Omron CX-Programmer project NewProject (CX-Programmer 9.33)

# PLC NewPLC1: CJ1M CPU13
I/O table (CPU CJ1M-CPU13): rack 0 slot 0 CJ1W-ID211; rack 0 slot 1 CJ1W-OC211; rack 0 slot 2 CJ1W-SCU32

## Global symbols (name address type ; comment)
1919.15 BOOL  ; $?St$Bk?_#[6] / Port 2 Protocol Macro Execution Flag / $?St$Bk?_#[6]
A202.00 BOOL  ; Communications Port Enabled Flag
A202.01 BOOL  ; Communications Port Enabled Flag
W0.00 BOOL  ; Execute Reading PV Of E5CN
W0.01 BOOL  ; Execute Writing SP Of E5CN
V1000_MoveVelocityHz_Node10 INV032_MoveVelocityHz
V1000_ReadParameter_Node10 INV201_ReadParameter
V1000_ReadStatus_Node10 INV200_ReadStatus
V1000_Refresh_Node10 INV002_Refresh
V1000_Reset_Node10 INV080_Reset
V1000_Stop_Node10 INV060_Stop

## Program NewProgram1 (cyclic task 0)

### Section E5CN

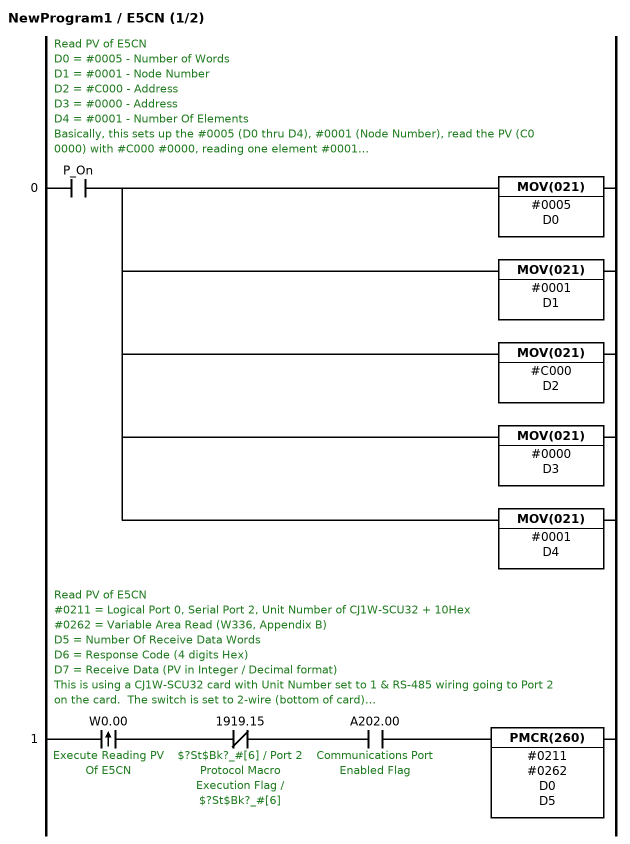
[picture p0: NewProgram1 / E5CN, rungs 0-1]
; rung 0: Read PV of E5CN / D0 = #0005 - Number of Words / D1 = #0001 - Node Number / D2 = #C000 - Address / D3 = #0000 - Address / D4 = #0001 - Number Of Elements / Basically, this sets up the #0005 (D0 thru D4), #0001 (Node Number), read the PV (C0 0000) with #C000 #0000, reading one element #0001. / C0 0000 is from manual H158, Section 3.1. / This rungs sets up the data for receiving the PV of the E5CN temperature controller at Node number 1 over Compoway/F communications.
LD P_On
MOV(021) #0005 D0
MOV(021) #0001 D1
MOV(021) #C000 D2
MOV(021) #0000 D3
MOV(021) #0001 D4
; rung 1: Read PV of E5CN / #0211 = Logical Port 0, Serial Port 2, Unit Number of CJ1W-SCU32 + 10Hex / #0262 = Variable Area Read (W336, Appendix B) / D5 = Number Of Receive Data Words / D6 = Response Code (4 digits Hex) / D7 = Receive Data (PV in Integer / Decimal format) / This is using a CJ1W-SCU32 card with Unit Number set to 1 & RS-485 wiring going to Port 2 on the card.  The switch is set to 2-wire (bottom of card). / Port Settings - User Settings / Serial Communications Mode - Protocol Macro / Data Length - 7 Bits / Stop Bits - 2 Bits / Parity - Even / Baud Rate - 9600
@LD W0.00  ; Execute Reading PV Of E5CN
ANDNOT 1919.15  ; $?St$Bk?_#[6] / Port 2 Protocol Macro Execution Flag / $?St$Bk?_#[6]
AND A202.00  ; Communications Port Enabled Flag
PMCR(260) #0211 #0262 D0 D5

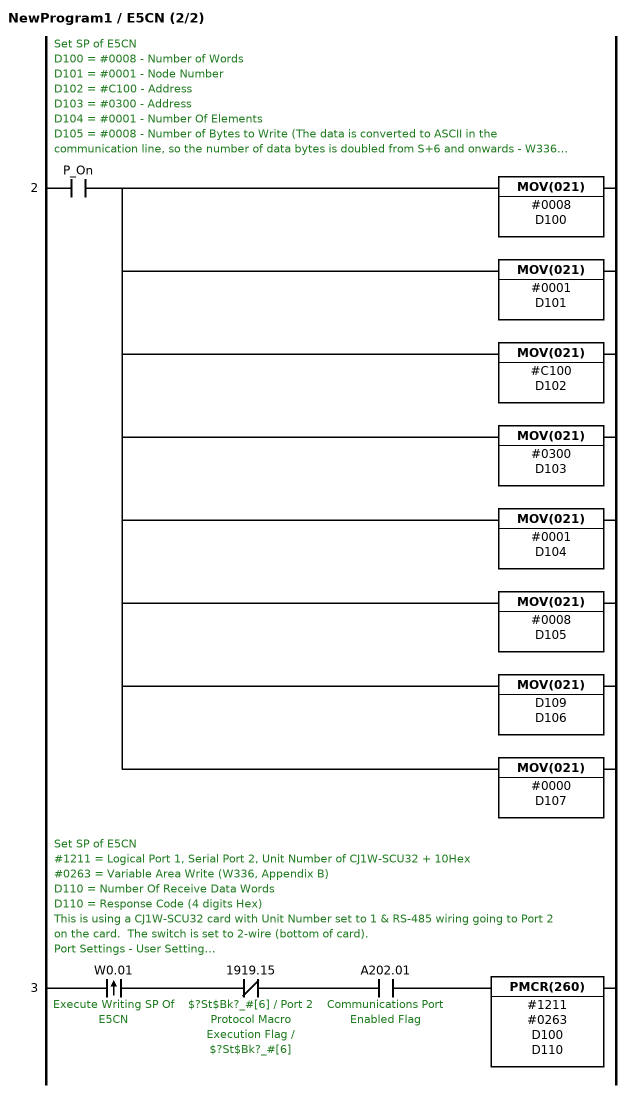
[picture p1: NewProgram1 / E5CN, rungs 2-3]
; rung 2: Set SP of E5CN / D100 = #0008 - Number of Words / D101 = #0001 - Node Number / D102 = #C100 - Address / D103 = #0300 - Address / D104 = #0001 - Number Of Elements / D105 = #0008 - Number of Bytes to Write (The data is converted to ASCII in the communication line, so the number of data bytes is doubled from S+6 and onwards - W336, Appendix B.) / D106 = D109 - LSW - Most Significant Word (Temperature Setpoint) / D107 = #0000 - MSW (Temperature Setpoint) / Basically, this sets up the #0008 (D100 thru D107), #0001 (Node Number), write the SP (C1 0003) with #C100 #0300, writing one element #0001. / C1 0003 is from manual H158, Section 3.1. / The data entered into D109 is in Integer / Decimal format. / This rungs sets up the data for sending the SP of the E5CN temperature controller at Node number 1 over Compoway/F communications.
LD P_On
MOV(021) #0008 D100
MOV(021) #0001 D101
MOV(021) #C100 D102
MOV(021) #0300 D103
MOV(021) #0001 D104
MOV(021) #0008 D105
MOV(021) D109 D106
MOV(021) #0000 D107
; rung 3: Set SP of E5CN / #1211 = Logical Port 1, Serial Port 2, Unit Number of CJ1W-SCU32 + 10Hex / #0263 = Variable Area Write (W336, Appendix B) / D110 = Number Of Receive Data Words / D110 = Response Code (4 digits Hex) / This is using a CJ1W-SCU32 card with Unit Number set to 1 & RS-485 wiring going to Port 2 on the card.  The switch is set to 2-wire (bottom of card). / Port Settings - User Settings / Serial Communications Mode - Protocol Macro / Data Length - 7 Bits / Stop Bits - 2 Bits / Parity - Even / Baud Rate - 9600
@LD W0.01  ; Execute Writing SP Of E5CN
ANDNOT 1919.15  ; $?St$Bk?_#[6] / Port 2 Protocol Macro Execution Flag / $?St$Bk?_#[6]
AND A202.01  ; Communications Port Enabled Flag
PMCR(260) #1211 #0263 D100 D110

### Section V1000

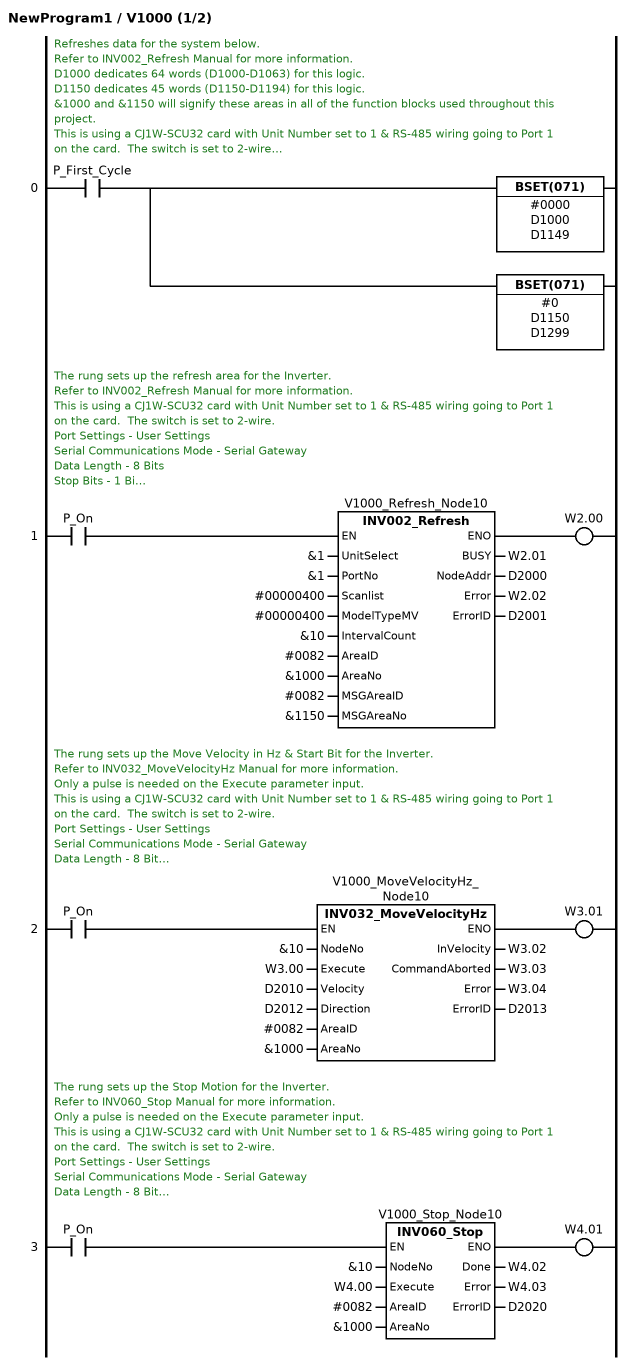
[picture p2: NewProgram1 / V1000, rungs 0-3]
; rung 0: Refreshes data for the system below. / Refer to INV002_Refresh Manual for more information. / D1000 dedicates 64 words (D1000-D1063) for this logic. / D1150 dedicates 45 words (D1150-D1194) for this logic. / &1000 and &1150 will signify these areas in all of the function blocks used throughout this project. / This is using a CJ1W-SCU32 card with Unit Number set to 1 & RS-485 wiring going to Port 1 on the card.  The switch is set to 2-wire. / Port Settings - User Settings / Serial Communications Mode - Serial Gateway / Data Length - 8 Bits / Stop Bits - 1 Bit / Parity - Even / Baud Rate - 9600
LD P_First_Cycle
BSET(071) #0000 D1000 D1149
BSET(071) #0 D1150 D1299
; rung 1: The rung sets up the refresh area for the Inverter. / Refer to INV002_Refresh Manual for more information. / This is using a CJ1W-SCU32 card with Unit Number set to 1 & RS-485 wiring going to Port 1 on the card.  The switch is set to 2-wire. / Port Settings - User Settings / Serial Communications Mode - Serial Gateway / Data Length - 8 Bits / Stop Bits - 1 Bit / Parity - Even / Baud Rate - 9600
LD P_On
CALL V1000_Refresh_Node10 : INV002_Refresh (UnitSelect := &1, PortNo := &1, Scanlist := #00000400, ModelTypeMV := #00000400, IntervalCount := &10, AreaID := #0082, AreaNo := &1000, MSGAreaID := #0082, MSGAreaNo := &1150, BUSY => W2.01, NodeAddr => D2000, Error => W2.02, ErrorID => D2001)
OUT W2.00
; rung 2: The rung sets up the Move Velocity in Hz & Start Bit for the Inverter. / Refer to INV032_MoveVelocityHz Manual for more information. / Only a pulse is needed on the Execute parameter input. / This is using a CJ1W-SCU32 card with Unit Number set to 1 & RS-485 wiring going to Port 1 on the card.  The switch is set to 2-wire. / Port Settings - User Settings / Serial Communications Mode - Serial Gateway / Data Length - 8 Bits / Stop Bits - 1 Bit / Parity - Even / Baud Rate - 9600
LD P_On
CALL V1000_MoveVelocityHz_Node10 : INV032_MoveVelocityHz (NodeNo := &10, Execute := W3.00, Velocity := D2010, Direction := D2012, AreaID := #0082, AreaNo := &1000, InVelocity => W3.02, CommandAborted => W3.03, Error => W3.04, ErrorID => D2013)
OUT W3.01
; rung 3: The rung sets up the Stop Motion for the Inverter. / Refer to INV060_Stop Manual for more information. / Only a pulse is needed on the Execute parameter input. / This is using a CJ1W-SCU32 card with Unit Number set to 1 & RS-485 wiring going to Port 1 on the card.  The switch is set to 2-wire. / Port Settings - User Settings / Serial Communications Mode - Serial Gateway / Data Length - 8 Bits / Stop Bits - 1 Bit / Parity - Even / Baud Rate - 9600
LD P_On
CALL V1000_Stop_Node10 : INV060_Stop (NodeNo := &10, Execute := W4.00, AreaID := #0082, AreaNo := &1000, Done => W4.02, Error => W4.03, ErrorID => D2020)
OUT W4.01

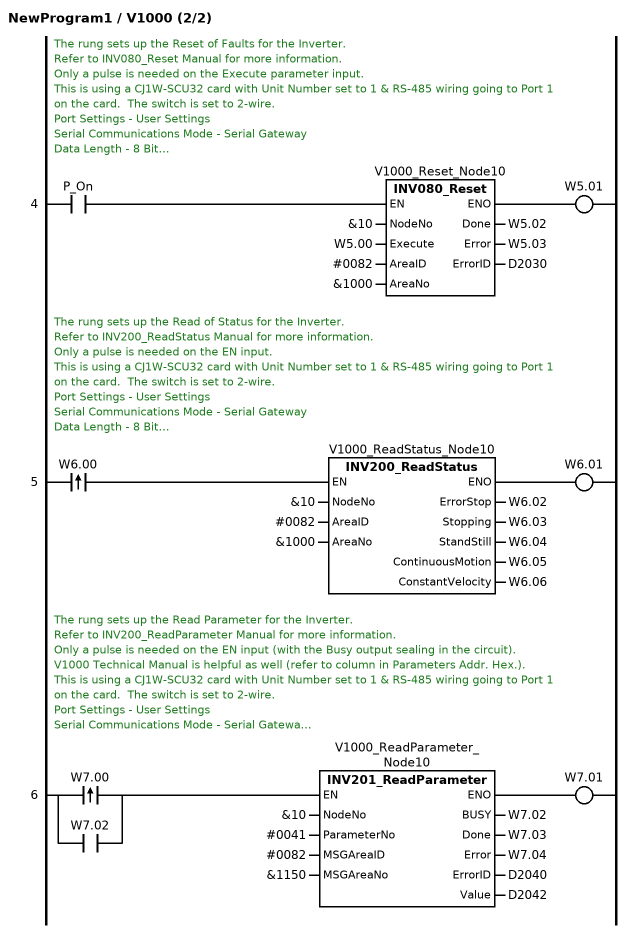
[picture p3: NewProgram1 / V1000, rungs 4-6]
; rung 4: The rung sets up the Reset of Faults for the Inverter. / Refer to INV080_Reset Manual for more information. / Only a pulse is needed on the Execute parameter input. / This is using a CJ1W-SCU32 card with Unit Number set to 1 & RS-485 wiring going to Port 1 on the card.  The switch is set to 2-wire. / Port Settings - User Settings / Serial Communications Mode - Serial Gateway / Data Length - 8 Bits / Stop Bits - 1 Bit / Parity - Even / Baud Rate - 9600
LD P_On
CALL V1000_Reset_Node10 : INV080_Reset (NodeNo := &10, Execute := W5.00, AreaID := #0082, AreaNo := &1000, Done => W5.02, Error => W5.03, ErrorID => D2030)
OUT W5.01
; rung 5: The rung sets up the Read of Status for the Inverter. / Refer to INV200_ReadStatus Manual for more information. / Only a pulse is needed on the EN input. / This is using a CJ1W-SCU32 card with Unit Number set to 1 & RS-485 wiring going to Port 1 on the card.  The switch is set to 2-wire. / Port Settings - User Settings / Serial Communications Mode - Serial Gateway / Data Length - 8 Bits / Stop Bits - 1 Bit / Parity - Even / Baud Rate - 9600
@LD W6.00
CALL V1000_ReadStatus_Node10 : INV200_ReadStatus (NodeNo := &10, AreaID := #0082, AreaNo := &1000, ErrorStop => W6.02, Stopping => W6.03, StandStill => W6.04, ContinuousMotion => W6.05, ConstantVelocity => W6.06)
OUT W6.01
; rung 6: The rung sets up the Read Parameter for the Inverter. / Refer to INV200_ReadParameter Manual for more information. / Only a pulse is needed on the EN input (with the Busy output sealing in the circuit). / V1000 Technical Manual is helpful as well (refer to column in Parameters Addr. Hex.). / This is using a CJ1W-SCU32 card with Unit Number set to 1 & RS-485 wiring going to Port 1 on the card.  The switch is set to 2-wire. / Port Settings - User Settings / Serial Communications Mode - Serial Gateway / Data Length - 8 Bits / Stop Bits - 1 Bit / Parity - Even / Baud Rate - 9600
@LD W7.00
OR W7.02
CALL V1000_ReadParameter_Node10 : INV201_ReadParameter (NodeNo := &10, ParameterNo := #0041, MSGAreaID := #0082, MSGAreaNo := &1150, BUSY => W7.02, Done => W7.03, Error => W7.04, ErrorID => D2040, Value => D2042)
OUT W7.01

### Section END
; rung 0
END(001)

## Function block INV002_Refresh
; <Status Refresh>Refreshes inverter status.
VAR_INPUT
  UnitSelect : INT;  (* Specify the connetcted Unit CP1CPU=#CCCC_SCB=#BBBB_SCU=&0 to &15 *)
  PortNo : INT := 1;  (* Serial port No. &1 to &2 *)
  Scanlist : DWORD;  (* Scanlist *)
  ModelTypeMV : DWORD;  (* MV/RV Classification *)
  IntervalCount : UINT;  (* Interval *)
  AreaID : WORD;  (* Using Area Classification *)
  AreaNo : INT;  (* Using Area Number *)
  MSGAreaID : WORD;  (* Message Area Classification *)
  MSGAreaNo : INT;  (* Message Area Number *)
END_VAR
VAR_OUTPUT
  BUSY : BOOL;  (* Processing Bit 0:Transferring Complete 1:Transferring *)
  NodeAddr : INT;  (* Executing Axis Number *)
  Error : BOOL;  (* Error *)
  ErrorID : WORD;  (* Error code *)
END_VAR
VAR
  AddressOk_Bit : BOOL;  (* Addrss Range Check OK Bit *)
  AreaID_Tmp : WORD;  (* Use Area Classification Memory (Internal Variables) *)
  AreaNo_Tmp : INT;  (* Use Area Number Memory (Internal Variables) *)
  BUSY_Run : BOOL;  (* Internal Processing Flag *)
  CMNDPort : INT;  (* Port Number 1(Automatic Setting) *)
  Command_CheckNo : INT;  (* Write Command Check Complete Number *)
  Command_Data : ARRAY[0..21] OF WORD;  (* CMND command data *)
  Command_Data_Change : BOOL;  (* Write Command Data Changing *)
  Command_Fin : BOOL;  (* CMND Transferring End *)
  Control_Data : ARRAY[0..5] OF WORD;  (* CMND control data *)
  Data_Change : BOOL;  (* Detect input data change *)
  Directive_Data : ARRAY[0..1] OF WORD;  (* Command data *)
  EM_NoCheck : INT;  (* EM bank size check area *)
  Error_Skip : BOOL;  (* Fatal Error Skip Flag *)
  FreeRunningCounter_Tmp : UINT;  (* 10ms free running incremental counter record *)
  Interval_Start : BOOL;  (* Interval Count Start *)
  Interval_TimeUp : BOOL;  (* Interval Time Up *)
  IntervalCount_Compare : INT;  (* Interval Compare Value *)
  IntervalCount_Tmp : UINT;  (* Interval Memory (Internal Variables) *)
  Inv_Command_Change_Position : INT;  (* Inverter Write Command Changing Position *)
  INV_Error : BOOL;  (* InverterNormal end *)
  Inv_NodeArea : ARRAY[0..31] OF WORD;  (* Applicable Axis Inverter Model and Number Store Area *)
  Inv_Status_Count : INT;  (* Inverter Status Command Execution Number *)
  Inv_Use_Count : INT;  (* Amount of Use Inverter Number *)
  Last_Area_Status : ARRAY[0..61] OF WORD;  (* The Last Time IOM Status Condition *)
  Message_Command_Done : BOOL;  (* Exist Message Command Flag *)
  ModelTypeMV_Tmp : DWORD;  (* MV/RV Classification Memory (Internal Variables) *)
  MSGAreaID_Tmp : WORD;  (* Message Area Classification Memory (Internal Variables) *)
  MSGAreaNo_Tmp : INT;  (* Message Area Number Memory (Internal Variables) *)
  NG_Bit : BOOL;  (* Range Check NG Bit *)
  No : INT;  (* MatrixNo *)
  Offset : DINT;  (* For Address Culcurate *)
  Ok_Bit : BOOL;  (* Range Check OK Bit *)
  Ok_DM : BOOL;  (* Selected DM area range OK *)
  Ok_EM : BOOL;  (* Selected EM area range OK *)
  Ok_HR : BOOL;  (* Selected HR area range OK *)
  Ok_IO : BOOL;  (* Selected CIO area range OK *)
  Ok_WR : BOOL;  (* Selected WR area range OK *)
  P_ComPort_AllocatedNumber AT A218 : INT;  (* Network port No. *)
  P_ComPort_AutoAlloc_Available AT A202.15 : BOOL;  (* Auto allocation avarable bit *)
  P_ComPort_Error AT A215 : WORD;  (* Communication Port No. 0 to 7 Error Bit *)
  P_ComPort_Finished0_7 AT A214 : WORD;  (* Communications Complete Cycle Bit *)
  P_ComPort_Retry AT A580 : WORD;  (* FB Communications command retry count *)
  P_ComPort_WatchResTime AT A581 : INT;  (* FB Communications command response Monitor time *)
  P_EM_MaxNo AT A338 : INT;  (* EM bank size *)
  P_Error : BOOL;  (* Error Bit *)
  P_FreeRunningCounter_10 AT A0 : UINT;  (* 10ms free running incremental counter *)
  Phase : WORD;  (* Process order *)
  PortNo_Tmp : INT;  (* Serial port No. storage(internal variables) *)
  Response_CodeNG : BOOL;  (* Response end code error *)
  Response_Data : ARRAY[0..20] OF WORD;  (* CMND response data *)
  Response_NG : BOOL;  (* Response error *)
  SaveDR : WORD;  (* DR0 *)
  SaveIR : ARRAY[0..3] OF DINT;  (* IR0 to IR3 *)
  Scanlist_Tmp : DWORD;  (* Scanlist Memory *)
  Set_IR AT 0 : WORD;  (* Index register temporary setting *)
  Status_2C : WORD;  (* Register2C  response data *)
  Status_Commmnd_Enable : BOOL;  (* Enable Execution Status Command *)
  Status_Commmnd_INT : BOOL;  (* Status Interrupt Flag *)
  Status_Inv_No : INT;  (* Status Command Slave Number *)
  Time_Value : UINT;  (* Interval Check Time Present Value *)
  Tmp_Data : ARRAY[0..30] OF WORD;  (* For internal Calculation *)
  Tmp_IR : ARRAY[0..3] OF DINT;  (* Temporary IR for internal variables *)
  Type_D AT D0 : WORD;  (* Address type DM start address *)
  Type_H AT H0 : WORD;  (* Address type HR start address *)
  Type_Io AT 0 : WORD;  (* Address type IO start address *)
  Type_W AT W0 : WORD;  (* Address type WR start address *)
  UnitSelect_Tmp : INT;  (* SCB/Select SCU Bit storage(internal variables) *)
  WAIT : BOOL;  (* First Cycle Wait Bit *)
END_VAR

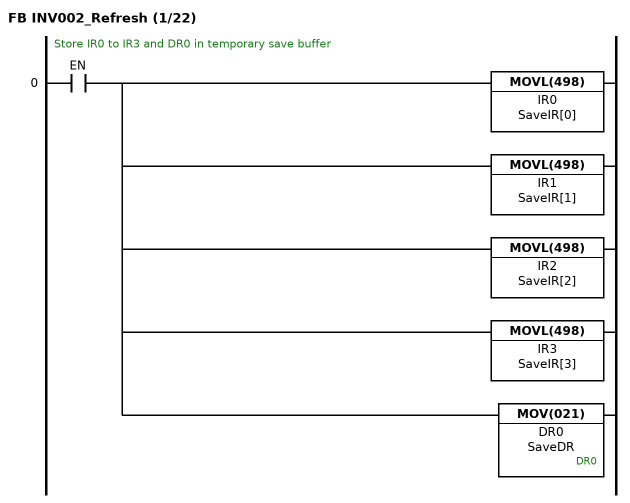
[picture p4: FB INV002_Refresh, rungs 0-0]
; rung 0: Store IR0 to IR3 and DR0 in temporary save buffer
LD EN
MOVL(498) IR0 SaveIR[0]
MOVL(498) IR1 SaveIR[1]
MOVL(498) IR2 SaveIR[2]
MOVL(498) IR3 SaveIR[3]
MOV(021) DR0 SaveDR  ; DR0

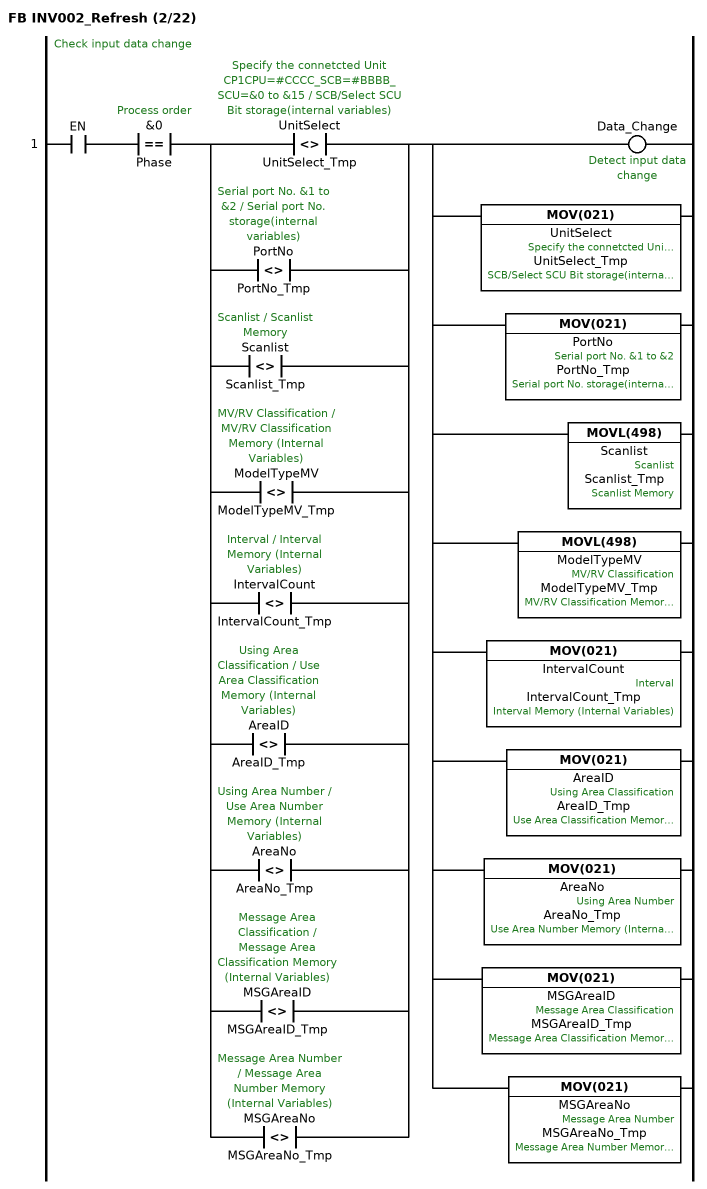
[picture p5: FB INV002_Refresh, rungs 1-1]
; rung 1: Check input data change
LD EN
AND=(300) &0 Phase  ; Process order
LD<>(305) UnitSelect UnitSelect_Tmp  ; Specify the connetcted Unit CP1CPU=#CCCC_SCB=#BBBB_SCU=&0 to &15, SCB/Select SCU Bit storage(internal variables)
OR<>(305) PortNo PortNo_Tmp  ; Serial port No. &1 to &2, Serial port No. storage(internal variables)
OR<>L(306) Scanlist Scanlist_Tmp  ; Scanlist, Scanlist Memory
OR<>L(306) ModelTypeMV ModelTypeMV_Tmp  ; MV/RV Classification, MV/RV Classification Memory (Internal Variables)
OR<>(305) IntervalCount IntervalCount_Tmp  ; Interval, Interval Memory (Internal Variables)
OR<>(305) AreaID AreaID_Tmp  ; Using Area Classification, Use Area Classification Memory (Internal Variables)
OR<>(305) AreaNo AreaNo_Tmp  ; Using Area Number, Use Area Number Memory (Internal Variables)
OR<>(305) MSGAreaID MSGAreaID_Tmp  ; Message Area Classification, Message Area Classification Memory (Internal Variables)
OR<>(305) MSGAreaNo MSGAreaNo_Tmp  ; Message Area Number, Message Area Number Memory (Internal Variables)
ANDLD
OUT Data_Change  ; Detect input data change
MOV(021) UnitSelect UnitSelect_Tmp  ; Specify the connetcted Unit CP1CPU=#CCCC_SCB=#BBBB_SCU=&0 to &15, SCB/Select SCU Bit storage(internal variables)
MOV(021) PortNo PortNo_Tmp  ; Serial port No. &1 to &2, Serial port No. storage(internal variables)
MOVL(498) Scanlist Scanlist_Tmp  ; Scanlist, Scanlist Memory
MOVL(498) ModelTypeMV ModelTypeMV_Tmp  ; MV/RV Classification, MV/RV Classification Memory (Internal Variables)
MOV(021) IntervalCount IntervalCount_Tmp  ; Interval, Interval Memory (Internal Variables)
MOV(021) AreaID AreaID_Tmp  ; Using Area Classification, Use Area Classification Memory (Internal Variables)
MOV(021) AreaNo AreaNo_Tmp  ; Using Area Number, Use Area Number Memory (Internal Variables)
MOV(021) MSGAreaID MSGAreaID_Tmp  ; Message Area Classification, Message Area Classification Memory (Internal Variables)
MOV(021) MSGAreaNo MSGAreaNo_Tmp  ; Message Area Number, Message Area Number Memory (Internal Variables)




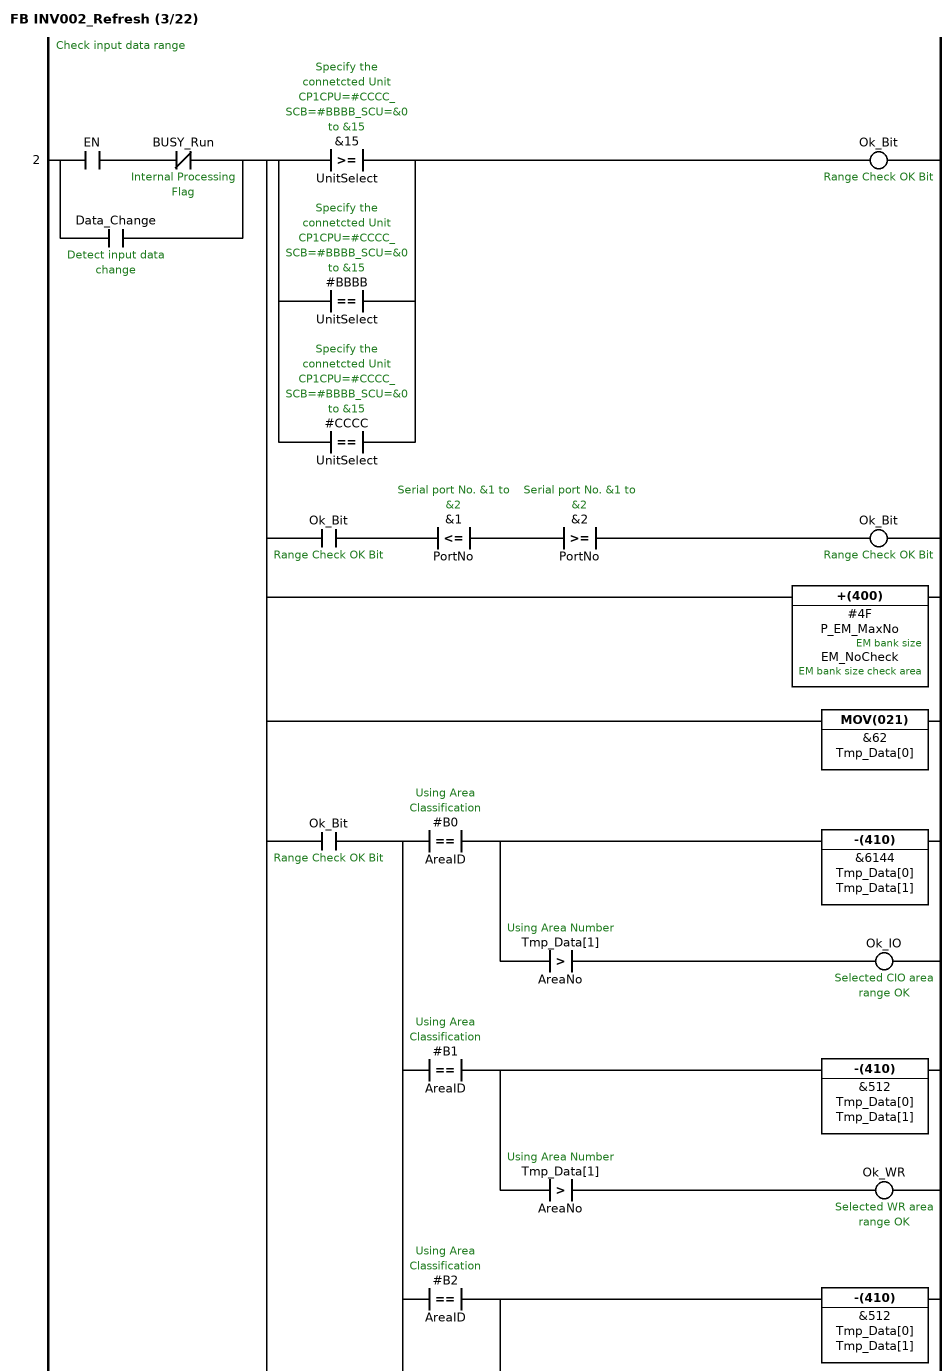
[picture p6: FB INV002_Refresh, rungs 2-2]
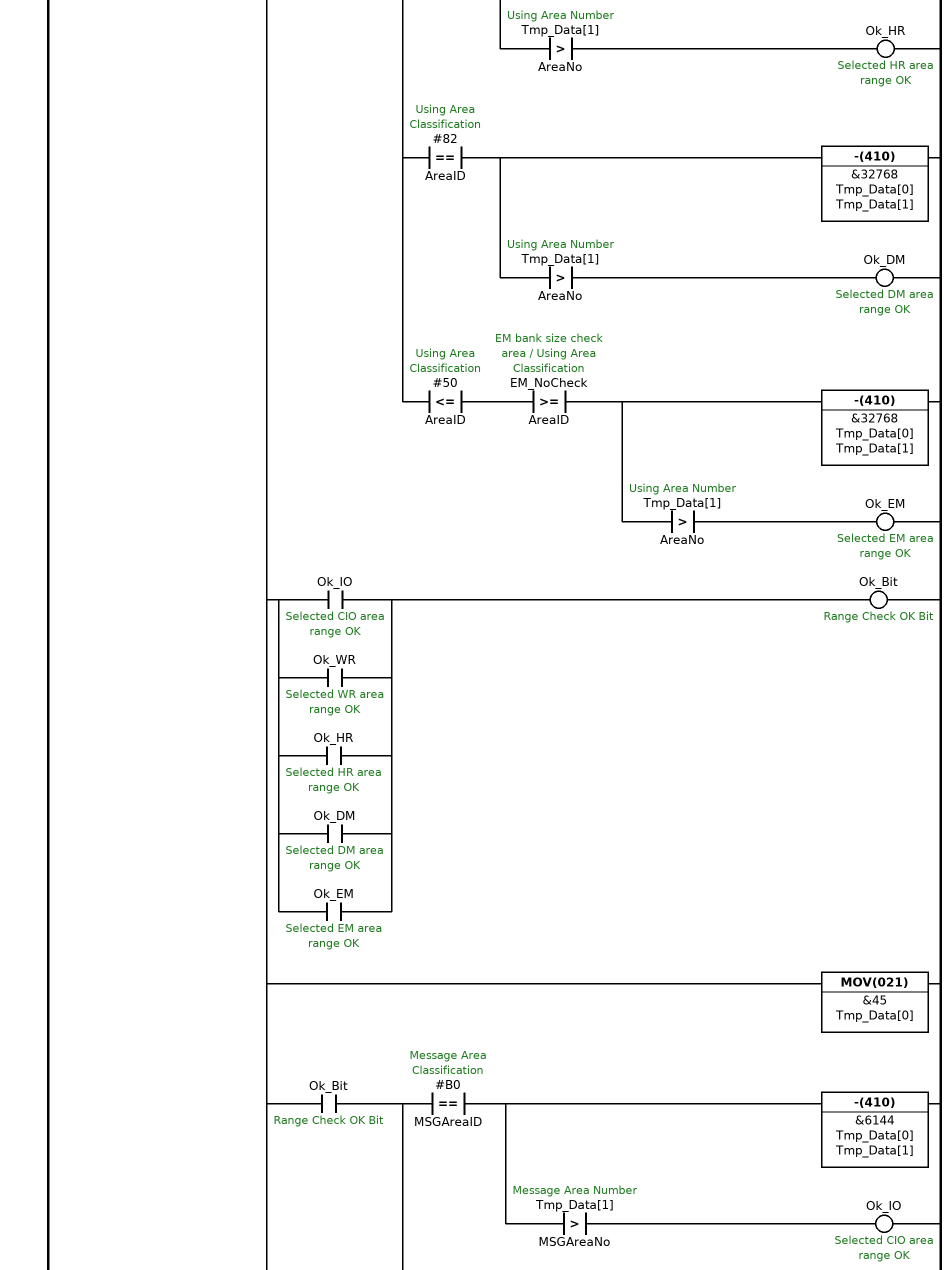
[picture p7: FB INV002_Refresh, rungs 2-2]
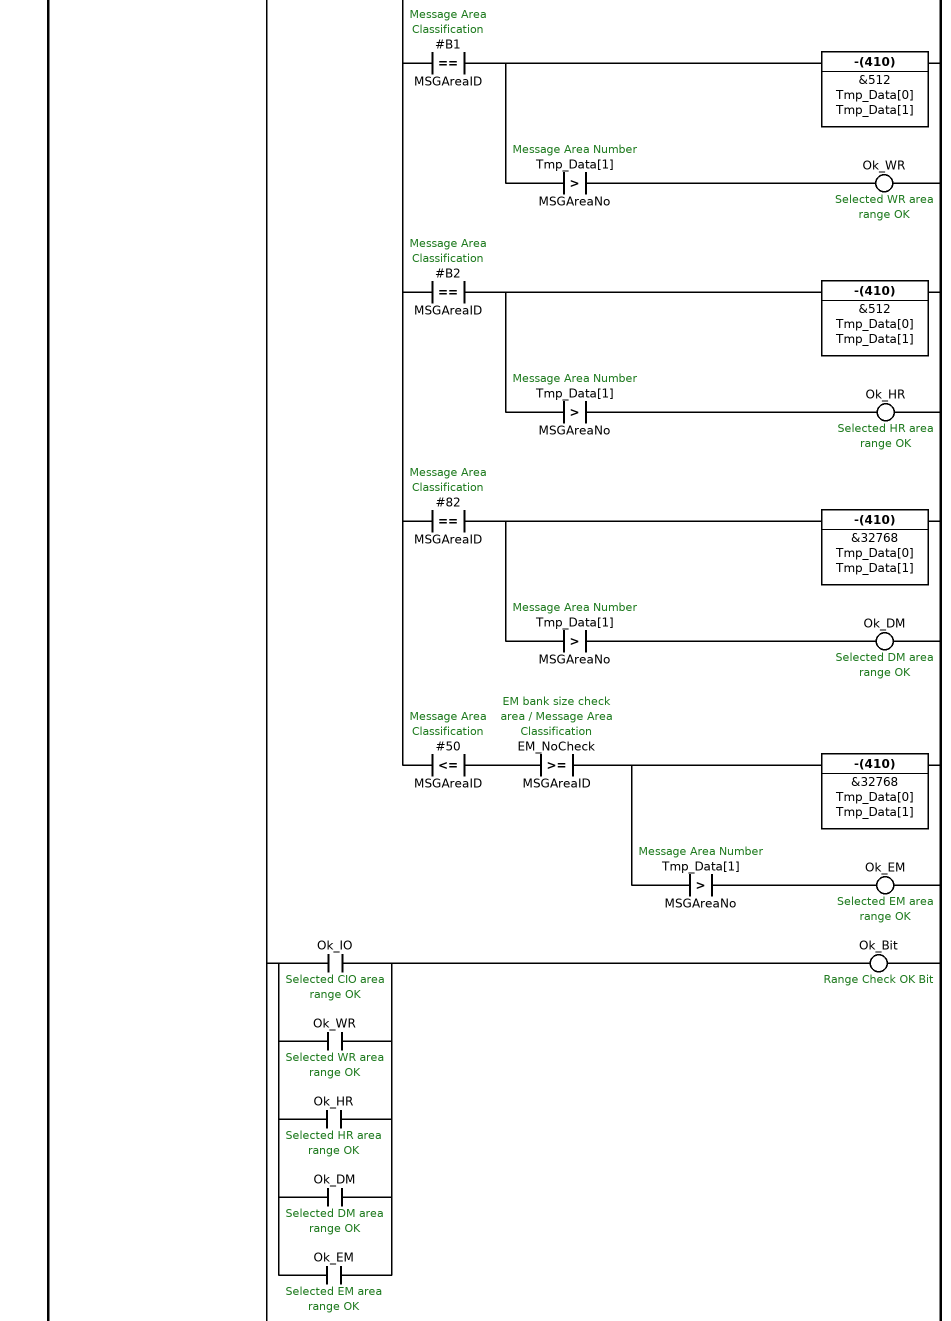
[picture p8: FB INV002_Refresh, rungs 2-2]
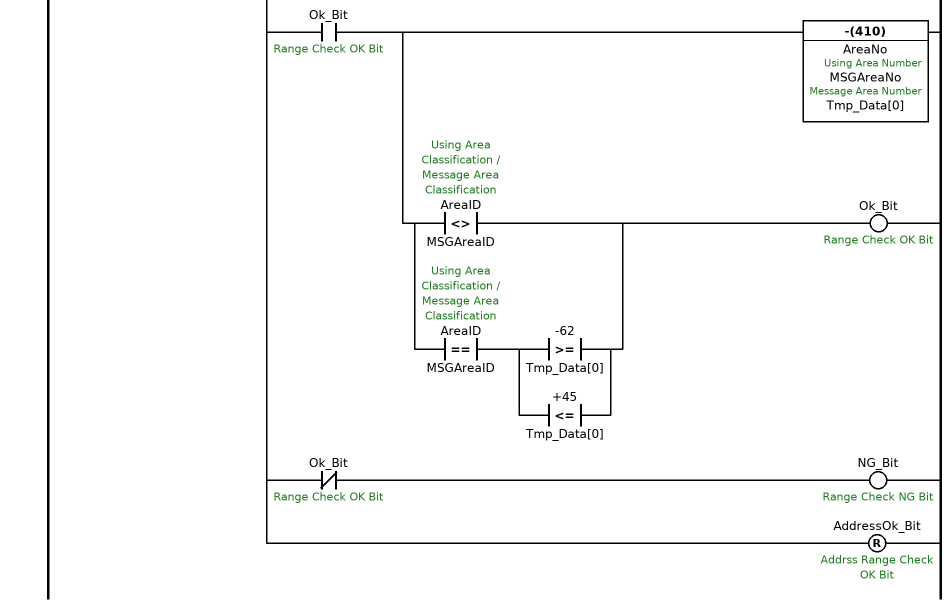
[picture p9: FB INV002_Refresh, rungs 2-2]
; rung 2: Check input data range
LD EN
ANDNOT BUSY_Run  ; Internal Processing Flag
OR Data_Change  ; Detect input data change
OUT TR0
LD>=(325) &15 UnitSelect  ; Specify the connetcted Unit CP1CPU=#CCCC_SCB=#BBBB_SCU=&0 to &15
OR=(300) #BBBB UnitSelect  ; Specify the connetcted Unit CP1CPU=#CCCC_SCB=#BBBB_SCU=&0 to &15
OR=(300) #CCCC UnitSelect  ; Specify the connetcted Unit CP1CPU=#CCCC_SCB=#BBBB_SCU=&0 to &15
ANDLD
OUT Ok_Bit  ; Range Check OK Bit
LD TR0
AND Ok_Bit  ; Range Check OK Bit
AND<=(315) &1 PortNo  ; Serial port No. &1 to &2
AND>=(325) &2 PortNo  ; Serial port No. &1 to &2
OUT Ok_Bit  ; Range Check OK Bit
LD TR0
+(400) #4F P_EM_MaxNo EM_NoCheck  ; EM bank size, EM bank size check area
MOV(021) &62 Tmp_Data[0]
AND Ok_Bit  ; Range Check OK Bit
OUT TR1
AND=(300) #B0 AreaID  ; Using Area Classification
-(410) &6144 Tmp_Data[0] Tmp_Data[1]
AND>(320) Tmp_Data[1] AreaNo  ; Using Area Number
OUT Ok_IO  ; Selected CIO area range OK
LD TR1
AND=(300) #B1 AreaID  ; Using Area Classification
-(410) &512 Tmp_Data[0] Tmp_Data[1]
AND>(320) Tmp_Data[1] AreaNo  ; Using Area Number
OUT Ok_WR  ; Selected WR area range OK
LD TR1
AND=(300) #B2 AreaID  ; Using Area Classification
-(410) &512 Tmp_Data[0] Tmp_Data[1]
AND>(320) Tmp_Data[1] AreaNo  ; Using Area Number
OUT Ok_HR  ; Selected HR area range OK
LD TR1
AND=(300) #82 AreaID  ; Using Area Classification
-(410) &32768 Tmp_Data[0] Tmp_Data[1]
AND>(320) Tmp_Data[1] AreaNo  ; Using Area Number
OUT Ok_DM  ; Selected DM area range OK
LD TR1
AND<=(315) #50 AreaID  ; Using Area Classification
AND>=(325) EM_NoCheck AreaID  ; EM bank size check area, Using Area Classification
-(410) &32768 Tmp_Data[0] Tmp_Data[1]
AND>(320) Tmp_Data[1] AreaNo  ; Using Area Number
OUT Ok_EM  ; Selected EM area range OK
LD TR0
LD Ok_IO  ; Selected CIO area range OK
OR Ok_WR  ; Selected WR area range OK
OR Ok_HR  ; Selected HR area range OK
OR Ok_DM  ; Selected DM area range OK
OR Ok_EM  ; Selected EM area range OK
ANDLD
OUT Ok_Bit  ; Range Check OK Bit
LD TR0
MOV(021) &45 Tmp_Data[0]
AND Ok_Bit  ; Range Check OK Bit
OUT TR2
AND=(300) #B0 MSGAreaID  ; Message Area Classification
-(410) &6144 Tmp_Data[0] Tmp_Data[1]
AND>(320) Tmp_Data[1] MSGAreaNo  ; Message Area Number
OUT Ok_IO  ; Selected CIO area range OK
LD TR2
AND=(300) #B1 MSGAreaID  ; Message Area Classification
-(410) &512 Tmp_Data[0] Tmp_Data[1]
AND>(320) Tmp_Data[1] MSGAreaNo  ; Message Area Number
OUT Ok_WR  ; Selected WR area range OK
LD TR2
AND=(300) #B2 MSGAreaID  ; Message Area Classification
-(410) &512 Tmp_Data[0] Tmp_Data[1]
AND>(320) Tmp_Data[1] MSGAreaNo  ; Message Area Number
OUT Ok_HR  ; Selected HR area range OK
LD TR2
AND=(300) #82 MSGAreaID  ; Message Area Classification
-(410) &32768 Tmp_Data[0] Tmp_Data[1]
AND>(320) Tmp_Data[1] MSGAreaNo  ; Message Area Number
OUT Ok_DM  ; Selected DM area range OK
LD TR2
AND<=(315) #50 MSGAreaID  ; Message Area Classification
AND>=(325) EM_NoCheck MSGAreaID  ; EM bank size check area, Message Area Classification
-(410) &32768 Tmp_Data[0] Tmp_Data[1]
AND>(320) Tmp_Data[1] MSGAreaNo  ; Message Area Number
OUT Ok_EM  ; Selected EM area range OK
LD TR0
LD Ok_IO  ; Selected CIO area range OK
OR Ok_WR  ; Selected WR area range OK
OR Ok_HR  ; Selected HR area range OK
OR Ok_DM  ; Selected DM area range OK
OR Ok_EM  ; Selected EM area range OK
ANDLD
OUT Ok_Bit  ; Range Check OK Bit
LD TR0
AND Ok_Bit  ; Range Check OK Bit
-(410) AreaNo MSGAreaNo Tmp_Data[0]  ; Using Area Number, Message Area Number
LD<>(305) AreaID MSGAreaID  ; Using Area Classification, Message Area Classification
LD=(300) AreaID MSGAreaID  ; Using Area Classification, Message Area Classification
LD>=S(327) -62 Tmp_Data[0]
OR<=S(317) +45 Tmp_Data[0]
ANDLD
ORLD
ANDLD
OUT Ok_Bit  ; Range Check OK Bit
LD TR0
ANDNOT Ok_Bit  ; Range Check OK Bit
OUT NG_Bit  ; Range Check NG Bit
LD TR0
RSET AddressOk_Bit  ; Addrss Range Check OK Bit

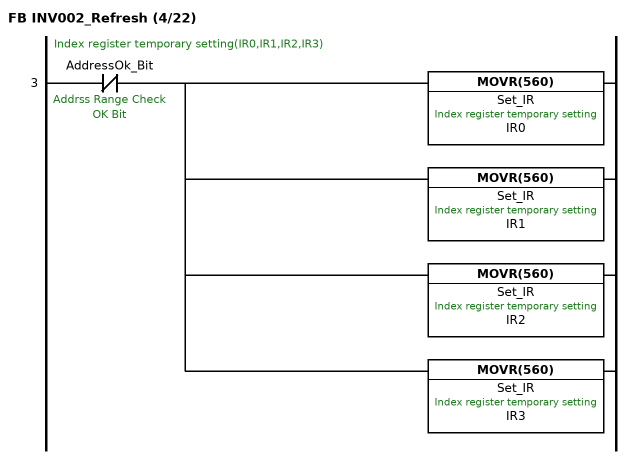
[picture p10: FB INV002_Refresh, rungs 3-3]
; rung 3: Index register temporary setting(IR0,IR1,IR2,IR3)
LDNOT AddressOk_Bit  ; Addrss Range Check OK Bit
MOVR(560) Set_IR IR0  ; Index register temporary setting
MOVR(560) Set_IR IR1  ; Index register temporary setting
MOVR(560) Set_IR IR2  ; Index register temporary setting
MOVR(560) Set_IR IR3  ; Index register temporary setting

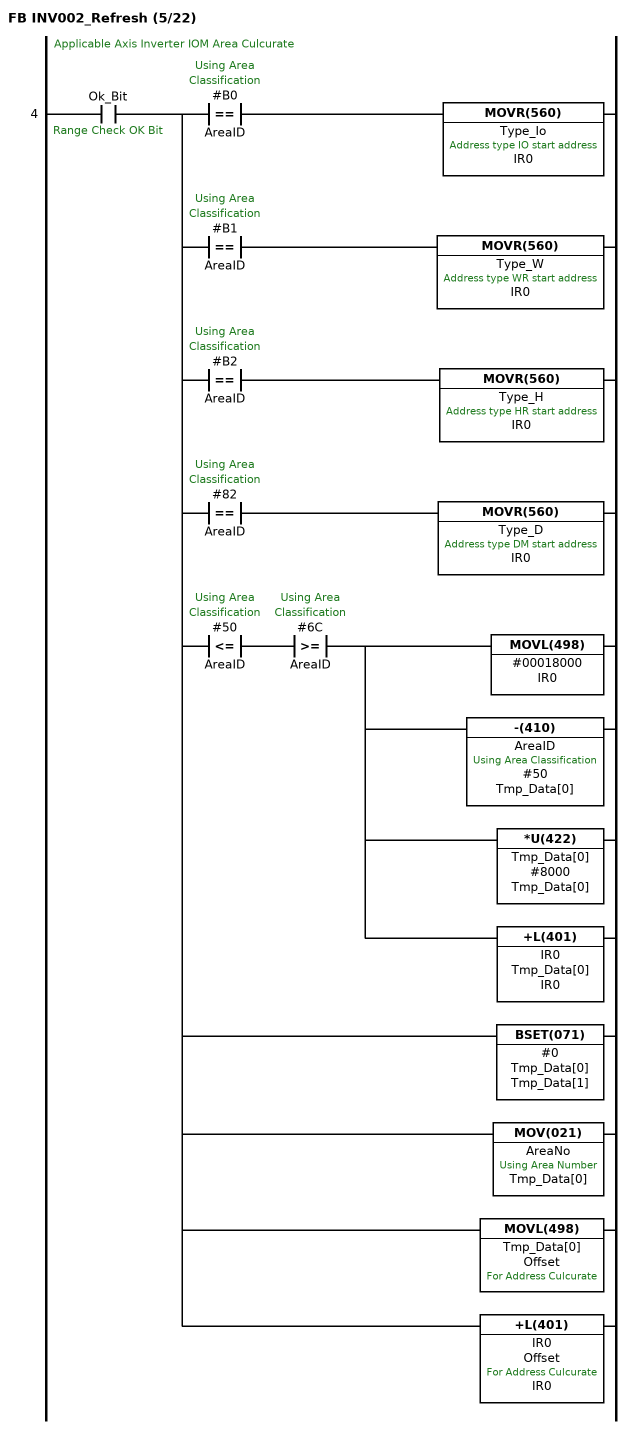
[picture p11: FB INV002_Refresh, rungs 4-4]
; rung 4: Applicable Axis Inverter IOM Area Culcurate
LD Ok_Bit  ; Range Check OK Bit
OUT TR0
AND=(300) #B0 AreaID  ; Using Area Classification
MOVR(560) Type_Io IR0  ; Address type IO start address
LD TR0
AND=(300) #B1 AreaID  ; Using Area Classification
MOVR(560) Type_W IR0  ; Address type WR start address
LD TR0
AND=(300) #B2 AreaID  ; Using Area Classification
MOVR(560) Type_H IR0  ; Address type HR start address
LD TR0
AND=(300) #82 AreaID  ; Using Area Classification
MOVR(560) Type_D IR0  ; Address type DM start address
LD TR0
AND<=(315) #50 AreaID  ; Using Area Classification
AND>=(325) #6C AreaID  ; Using Area Classification
MOVL(498) #00018000 IR0
-(410) AreaID #50 Tmp_Data[0]  ; Using Area Classification
*U(422) Tmp_Data[0] #8000 Tmp_Data[0]
+L(401) IR0 Tmp_Data[0] IR0
LD TR0
BSET(071) #0 Tmp_Data[0] Tmp_Data[1]
MOV(021) AreaNo Tmp_Data[0]  ; Using Area Number
MOVL(498) Tmp_Data[0] Offset  ; For Address Culcurate
+L(401) IR0 Offset IR0  ; For Address Culcurate

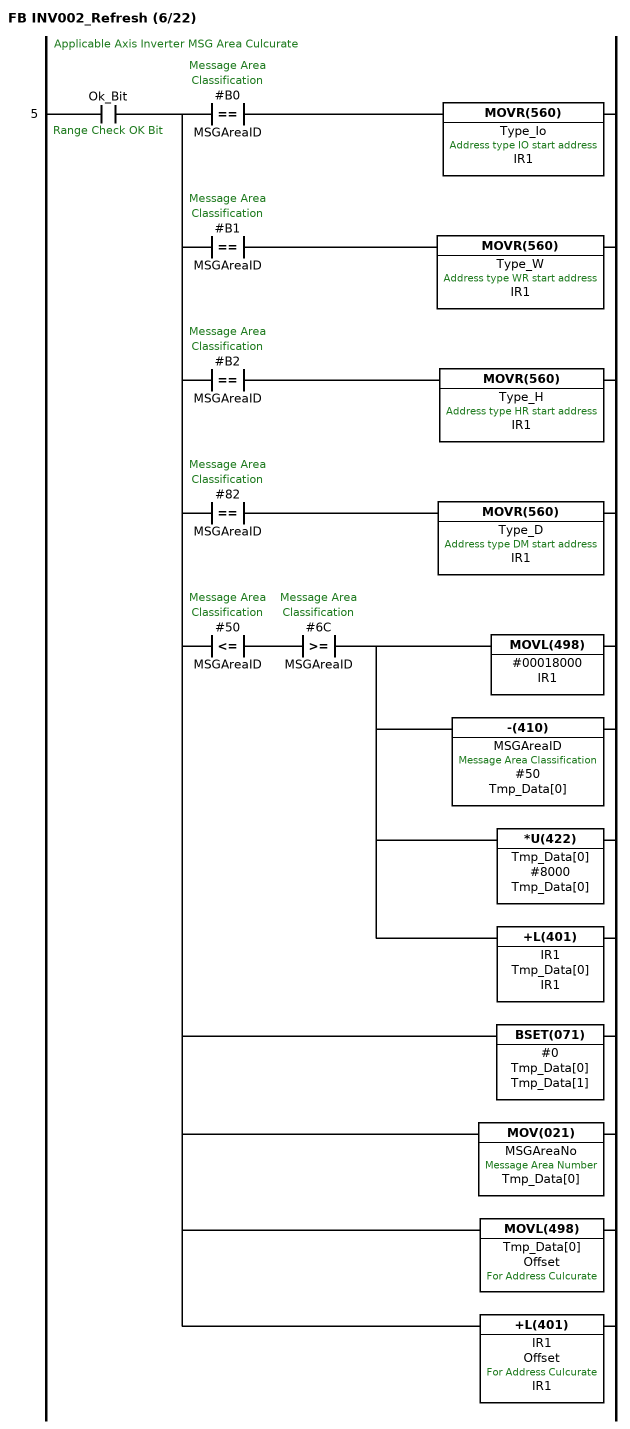
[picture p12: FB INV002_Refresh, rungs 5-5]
; rung 5: Applicable Axis Inverter MSG Area Culcurate
LD Ok_Bit  ; Range Check OK Bit
OUT TR0
AND=(300) #B0 MSGAreaID  ; Message Area Classification
MOVR(560) Type_Io IR1  ; Address type IO start address
LD TR0
AND=(300) #B1 MSGAreaID  ; Message Area Classification
MOVR(560) Type_W IR1  ; Address type WR start address
LD TR0
AND=(300) #B2 MSGAreaID  ; Message Area Classification
MOVR(560) Type_H IR1  ; Address type HR start address
LD TR0
AND=(300) #82 MSGAreaID  ; Message Area Classification
MOVR(560) Type_D IR1  ; Address type DM start address
LD TR0
AND<=(315) #50 MSGAreaID  ; Message Area Classification
AND>=(325) #6C MSGAreaID  ; Message Area Classification
MOVL(498) #00018000 IR1
-(410) MSGAreaID #50 Tmp_Data[0]  ; Message Area Classification
*U(422) Tmp_Data[0] #8000 Tmp_Data[0]
+L(401) IR1 Tmp_Data[0] IR1
LD TR0
BSET(071) #0 Tmp_Data[0] Tmp_Data[1]
MOV(021) MSGAreaNo Tmp_Data[0]  ; Message Area Number
MOVL(498) Tmp_Data[0] Offset  ; For Address Culcurate
+L(401) IR1 Offset IR1  ; For Address Culcurate

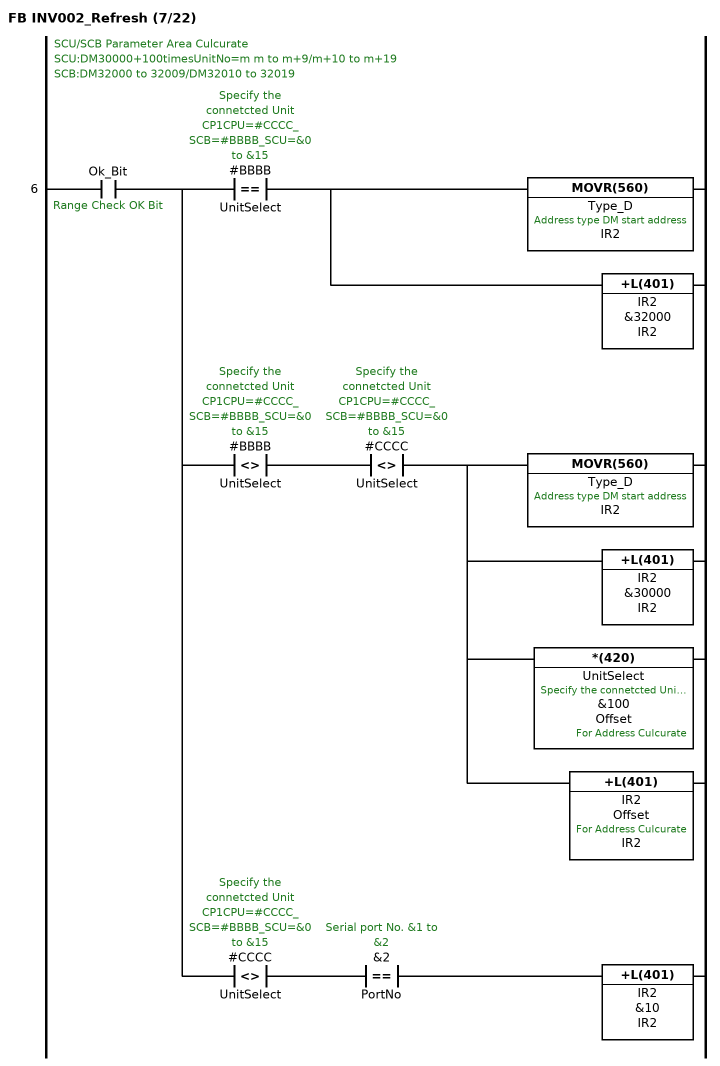
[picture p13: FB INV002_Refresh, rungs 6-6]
; rung 6: SCU/SCB Parameter Area Culcurate / SCU:DM30000+100timesUnitNo=m m to m+9/m+10 to m+19 / SCB:DM32000 to 32009/DM32010 to 32019
LD Ok_Bit  ; Range Check OK Bit
OUT TR0
AND=(300) #BBBB UnitSelect  ; Specify the connetcted Unit CP1CPU=#CCCC_SCB=#BBBB_SCU=&0 to &15
MOVR(560) Type_D IR2  ; Address type DM start address
+L(401) IR2 &32000 IR2
LD TR0
AND<>(305) #BBBB UnitSelect  ; Specify the connetcted Unit CP1CPU=#CCCC_SCB=#BBBB_SCU=&0 to &15
AND<>(305) #CCCC UnitSelect  ; Specify the connetcted Unit CP1CPU=#CCCC_SCB=#BBBB_SCU=&0 to &15
MOVR(560) Type_D IR2  ; Address type DM start address
+L(401) IR2 &30000 IR2
*(420) UnitSelect &100 Offset  ; Specify the connetcted Unit CP1CPU=#CCCC_SCB=#BBBB_SCU=&0 to &15, For Address Culcurate
+L(401) IR2 Offset IR2  ; For Address Culcurate
LD TR0
AND<>(305) #CCCC UnitSelect  ; Specify the connetcted Unit CP1CPU=#CCCC_SCB=#BBBB_SCU=&0 to &15
AND=(300) &2 PortNo  ; Serial port No. &1 to &2
+L(401) IR2 &10 IR2

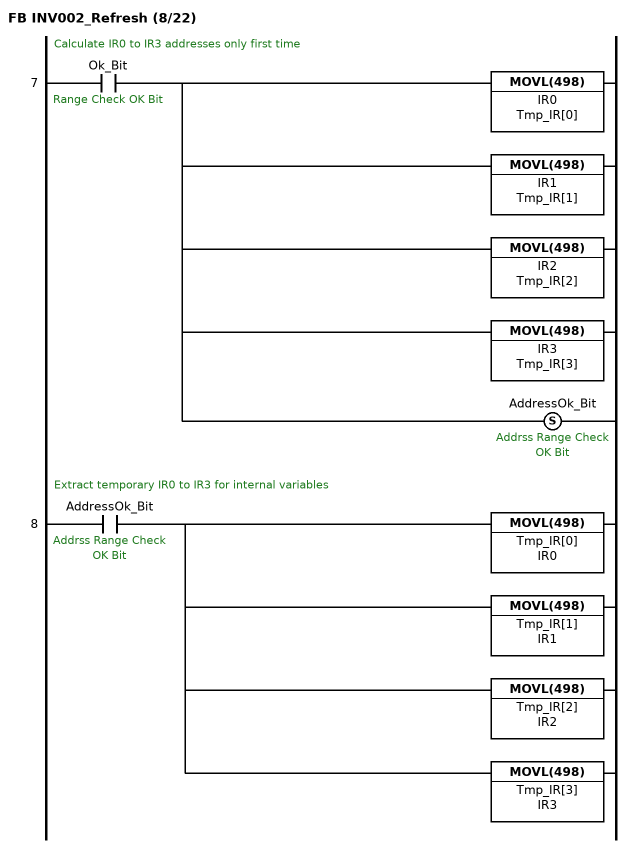
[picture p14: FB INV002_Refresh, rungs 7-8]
; rung 7: Calculate IR0 to IR3 addresses only first time
LD Ok_Bit  ; Range Check OK Bit
MOVL(498) IR0 Tmp_IR[0]
MOVL(498) IR1 Tmp_IR[1]
MOVL(498) IR2 Tmp_IR[2]
MOVL(498) IR3 Tmp_IR[3]
SET AddressOk_Bit  ; Addrss Range Check OK Bit
; rung 8: Extract temporary IR0 to IR3 for internal variables
LD AddressOk_Bit  ; Addrss Range Check OK Bit
MOVL(498) Tmp_IR[0] IR0
MOVL(498) Tmp_IR[1] IR1
MOVL(498) Tmp_IR[2] IR2
MOVL(498) Tmp_IR[3] IR3




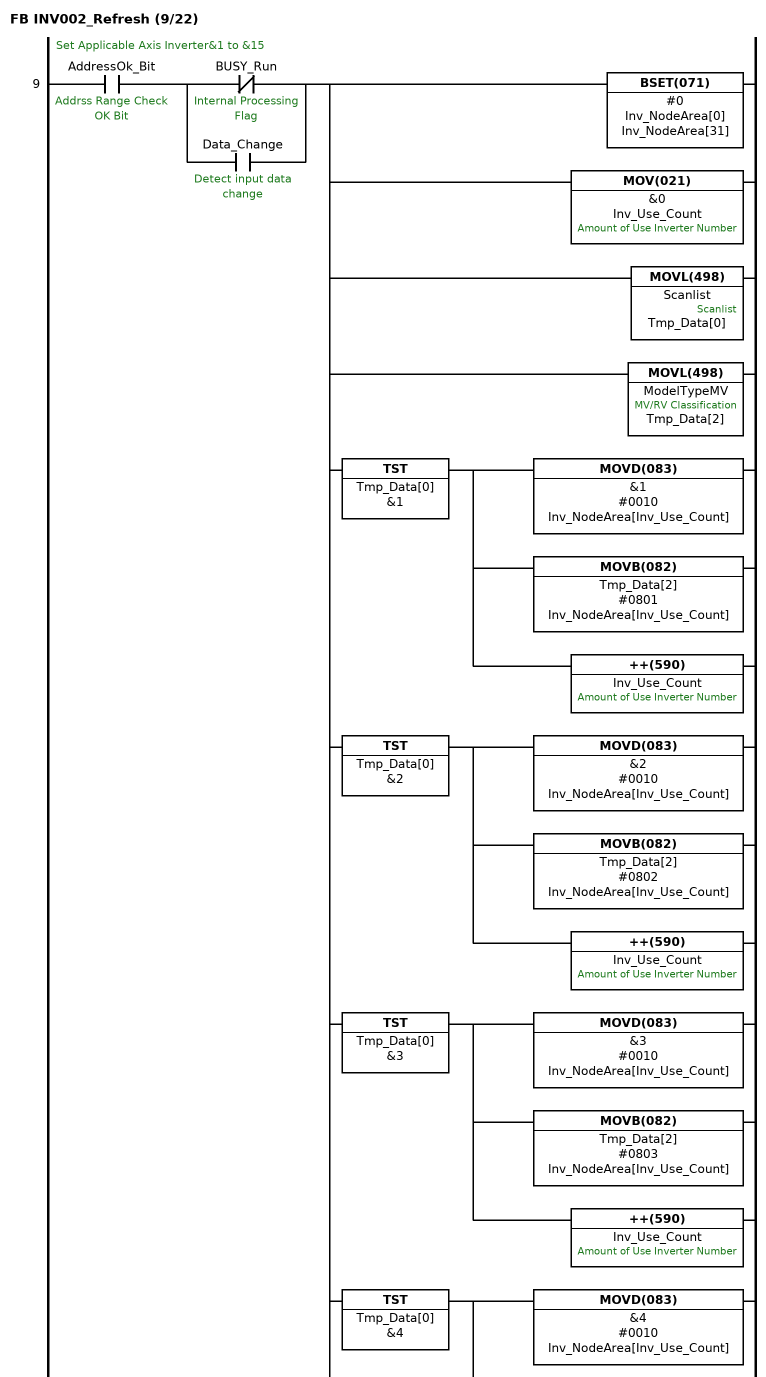
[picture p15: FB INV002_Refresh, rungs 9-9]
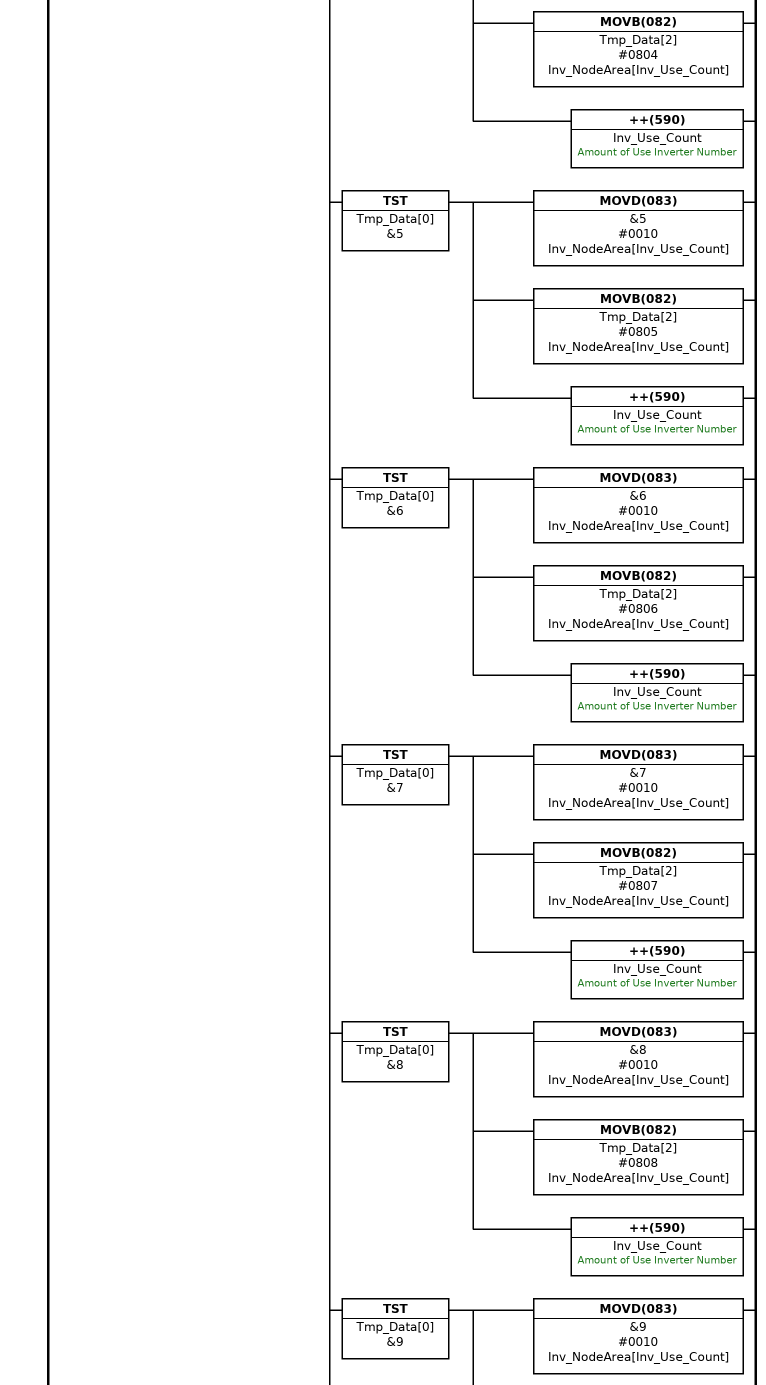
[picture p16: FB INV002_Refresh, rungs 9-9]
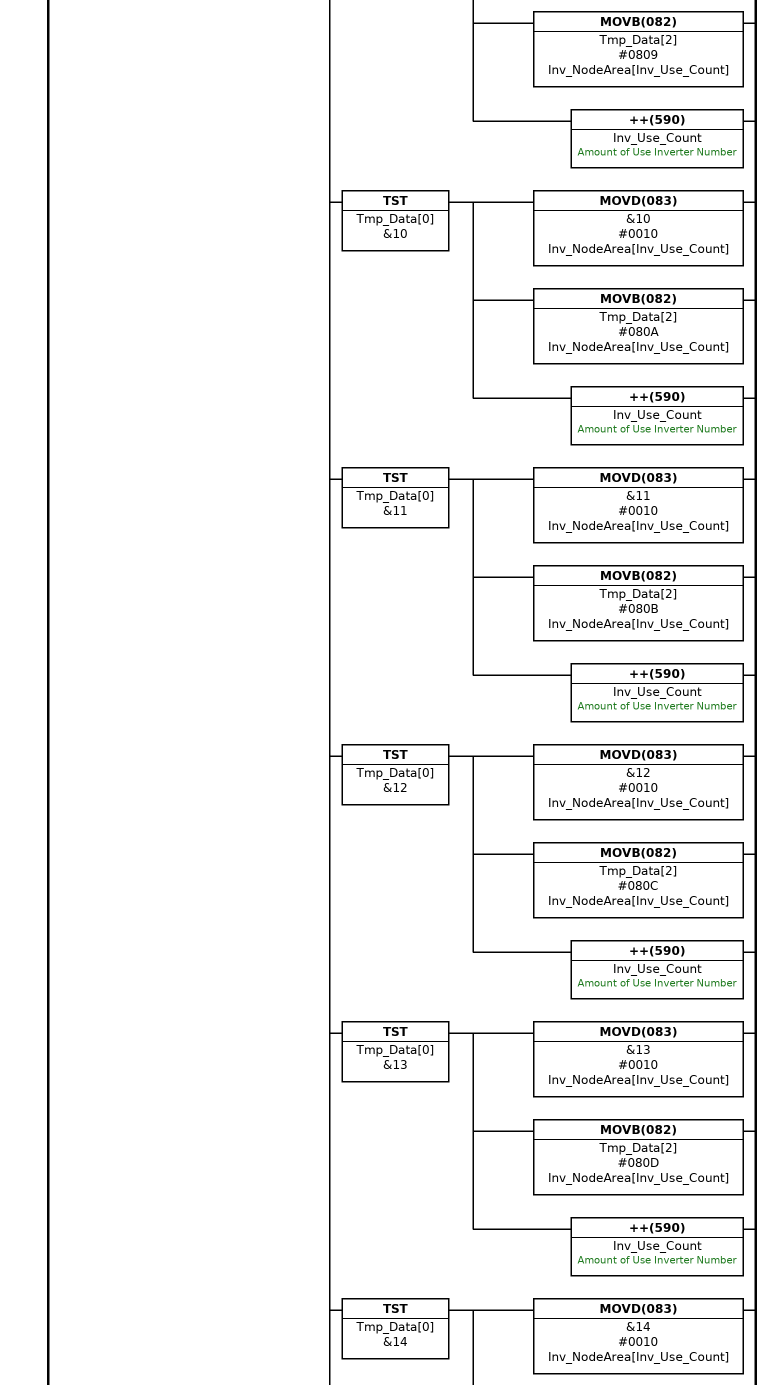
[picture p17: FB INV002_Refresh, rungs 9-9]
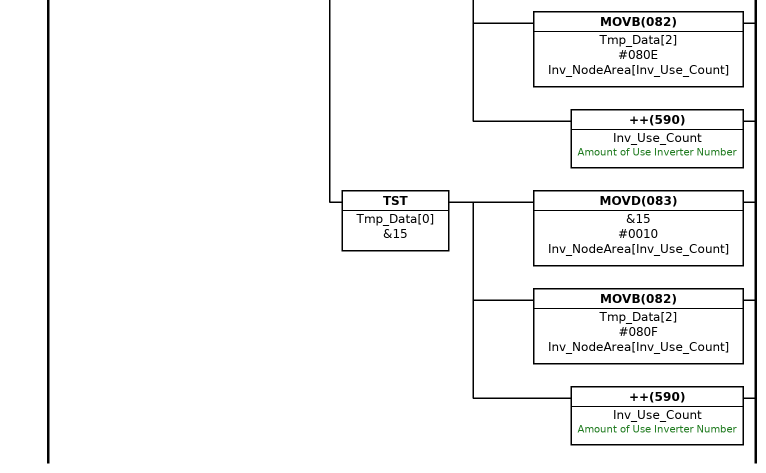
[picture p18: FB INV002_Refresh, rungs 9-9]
; rung 9: Set Applicable Axis Inverter&1 to &15
LD AddressOk_Bit  ; Addrss Range Check OK Bit
LDNOT BUSY_Run  ; Internal Processing Flag
OR Data_Change  ; Detect input data change
ANDLD
OUT TR0
BSET(071) #0 Inv_NodeArea[0] Inv_NodeArea[31]
MOV(021) &0 Inv_Use_Count  ; Amount of Use Inverter Number
MOVL(498) Scanlist Tmp_Data[0]  ; Scanlist
MOVL(498) ModelTypeMV Tmp_Data[2]  ; MV/RV Classification
ANDTST(350) Tmp_Data[0] &1
MOVD(083) &1 #0010 Inv_NodeArea[Inv_Use_Count]
MOVB(082) Tmp_Data[2] #0801 Inv_NodeArea[Inv_Use_Count]
++(590) Inv_Use_Count  ; Amount of Use Inverter Number
LD TR0
ANDTST(350) Tmp_Data[0] &2
MOVD(083) &2 #0010 Inv_NodeArea[Inv_Use_Count]
MOVB(082) Tmp_Data[2] #0802 Inv_NodeArea[Inv_Use_Count]
++(590) Inv_Use_Count  ; Amount of Use Inverter Number
LD TR0
ANDTST(350) Tmp_Data[0] &3
MOVD(083) &3 #0010 Inv_NodeArea[Inv_Use_Count]
MOVB(082) Tmp_Data[2] #0803 Inv_NodeArea[Inv_Use_Count]
++(590) Inv_Use_Count  ; Amount of Use Inverter Number
LD TR0
ANDTST(350) Tmp_Data[0] &4
MOVD(083) &4 #0010 Inv_NodeArea[Inv_Use_Count]
MOVB(082) Tmp_Data[2] #0804 Inv_NodeArea[Inv_Use_Count]
++(590) Inv_Use_Count  ; Amount of Use Inverter Number
LD TR0
ANDTST(350) Tmp_Data[0] &5
MOVD(083) &5 #0010 Inv_NodeArea[Inv_Use_Count]
MOVB(082) Tmp_Data[2] #0805 Inv_NodeArea[Inv_Use_Count]
++(590) Inv_Use_Count  ; Amount of Use Inverter Number
LD TR0
ANDTST(350) Tmp_Data[0] &6
MOVD(083) &6 #0010 Inv_NodeArea[Inv_Use_Count]
MOVB(082) Tmp_Data[2] #0806 Inv_NodeArea[Inv_Use_Count]
++(590) Inv_Use_Count  ; Amount of Use Inverter Number
LD TR0
ANDTST(350) Tmp_Data[0] &7
MOVD(083) &7 #0010 Inv_NodeArea[Inv_Use_Count]
MOVB(082) Tmp_Data[2] #0807 Inv_NodeArea[Inv_Use_Count]
++(590) Inv_Use_Count  ; Amount of Use Inverter Number
LD TR0
ANDTST(350) Tmp_Data[0] &8
MOVD(083) &8 #0010 Inv_NodeArea[Inv_Use_Count]
MOVB(082) Tmp_Data[2] #0808 Inv_NodeArea[Inv_Use_Count]
++(590) Inv_Use_Count  ; Amount of Use Inverter Number
LD TR0
ANDTST(350) Tmp_Data[0] &9
MOVD(083) &9 #0010 Inv_NodeArea[Inv_Use_Count]
MOVB(082) Tmp_Data[2] #0809 Inv_NodeArea[Inv_Use_Count]
++(590) Inv_Use_Count  ; Amount of Use Inverter Number
LD TR0
ANDTST(350) Tmp_Data[0] &10
MOVD(083) &10 #0010 Inv_NodeArea[Inv_Use_Count]
MOVB(082) Tmp_Data[2] #080A Inv_NodeArea[Inv_Use_Count]
++(590) Inv_Use_Count  ; Amount of Use Inverter Number
LD TR0
ANDTST(350) Tmp_Data[0] &11
MOVD(083) &11 #0010 Inv_NodeArea[Inv_Use_Count]
MOVB(082) Tmp_Data[2] #080B Inv_NodeArea[Inv_Use_Count]
++(590) Inv_Use_Count  ; Amount of Use Inverter Number
LD TR0
ANDTST(350) Tmp_Data[0] &12
MOVD(083) &12 #0010 Inv_NodeArea[Inv_Use_Count]
MOVB(082) Tmp_Data[2] #080C Inv_NodeArea[Inv_Use_Count]
++(590) Inv_Use_Count  ; Amount of Use Inverter Number
LD TR0
ANDTST(350) Tmp_Data[0] &13
MOVD(083) &13 #0010 Inv_NodeArea[Inv_Use_Count]
MOVB(082) Tmp_Data[2] #080D Inv_NodeArea[Inv_Use_Count]
++(590) Inv_Use_Count  ; Amount of Use Inverter Number
LD TR0
ANDTST(350) Tmp_Data[0] &14
MOVD(083) &14 #0010 Inv_NodeArea[Inv_Use_Count]
MOVB(082) Tmp_Data[2] #080E Inv_NodeArea[Inv_Use_Count]
++(590) Inv_Use_Count  ; Amount of Use Inverter Number
LD TR0
ANDTST(350) Tmp_Data[0] &15
MOVD(083) &15 #0010 Inv_NodeArea[Inv_Use_Count]
MOVB(082) Tmp_Data[2] #080F Inv_NodeArea[Inv_Use_Count]
++(590) Inv_Use_Count  ; Amount of Use Inverter Number




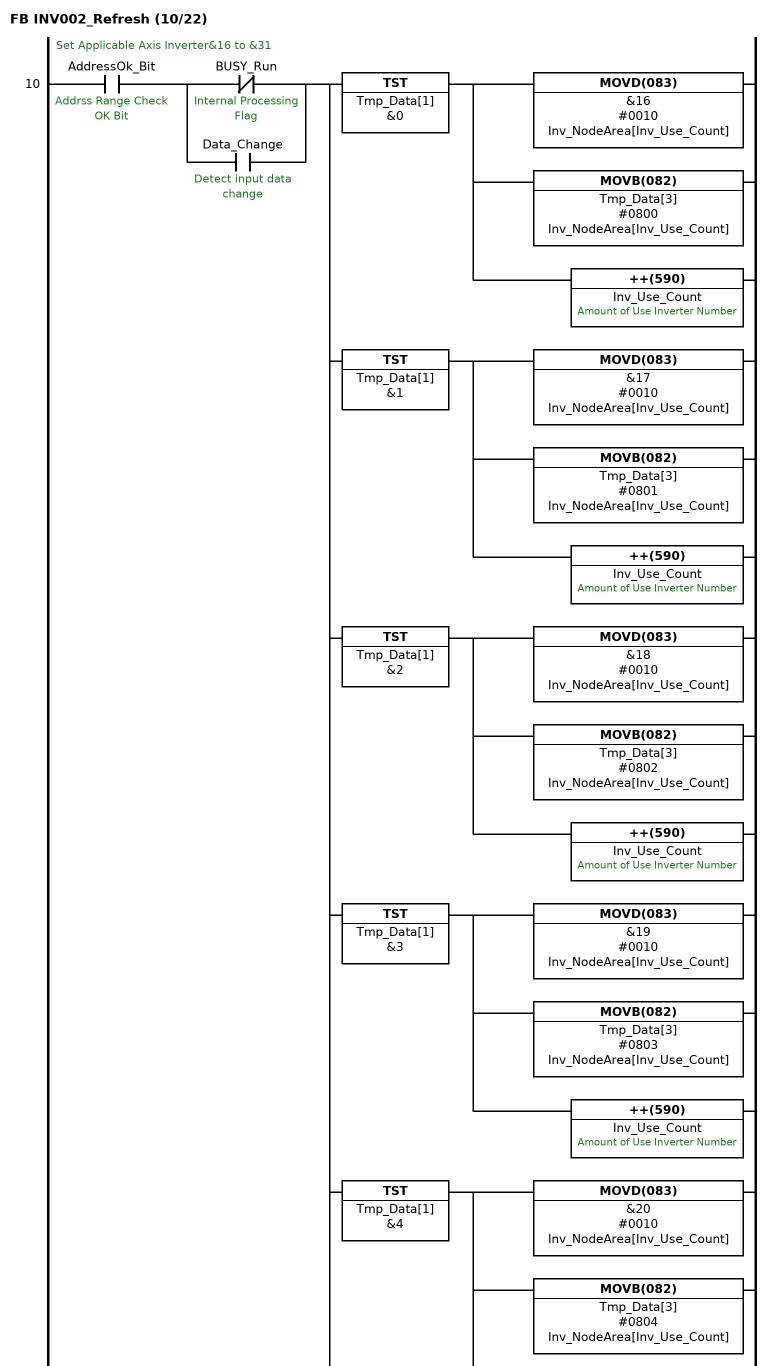
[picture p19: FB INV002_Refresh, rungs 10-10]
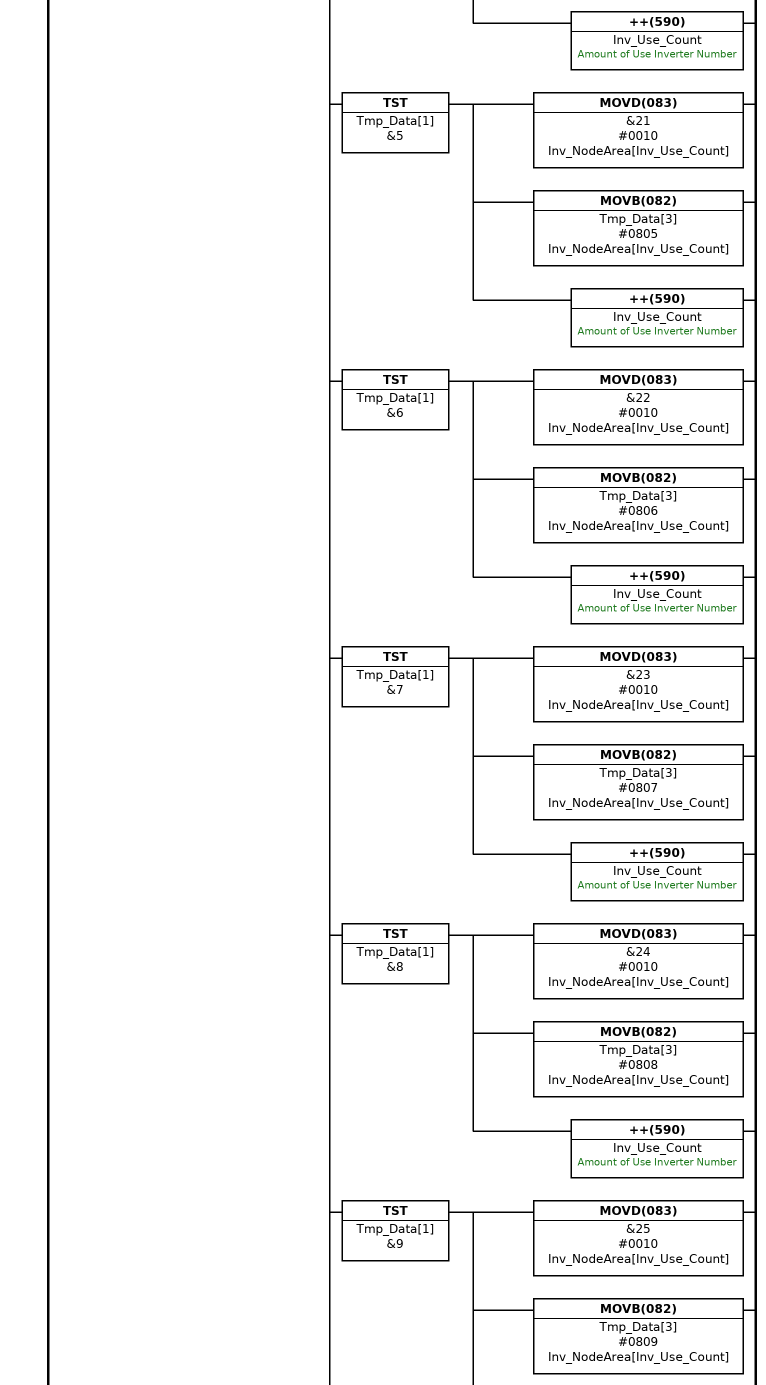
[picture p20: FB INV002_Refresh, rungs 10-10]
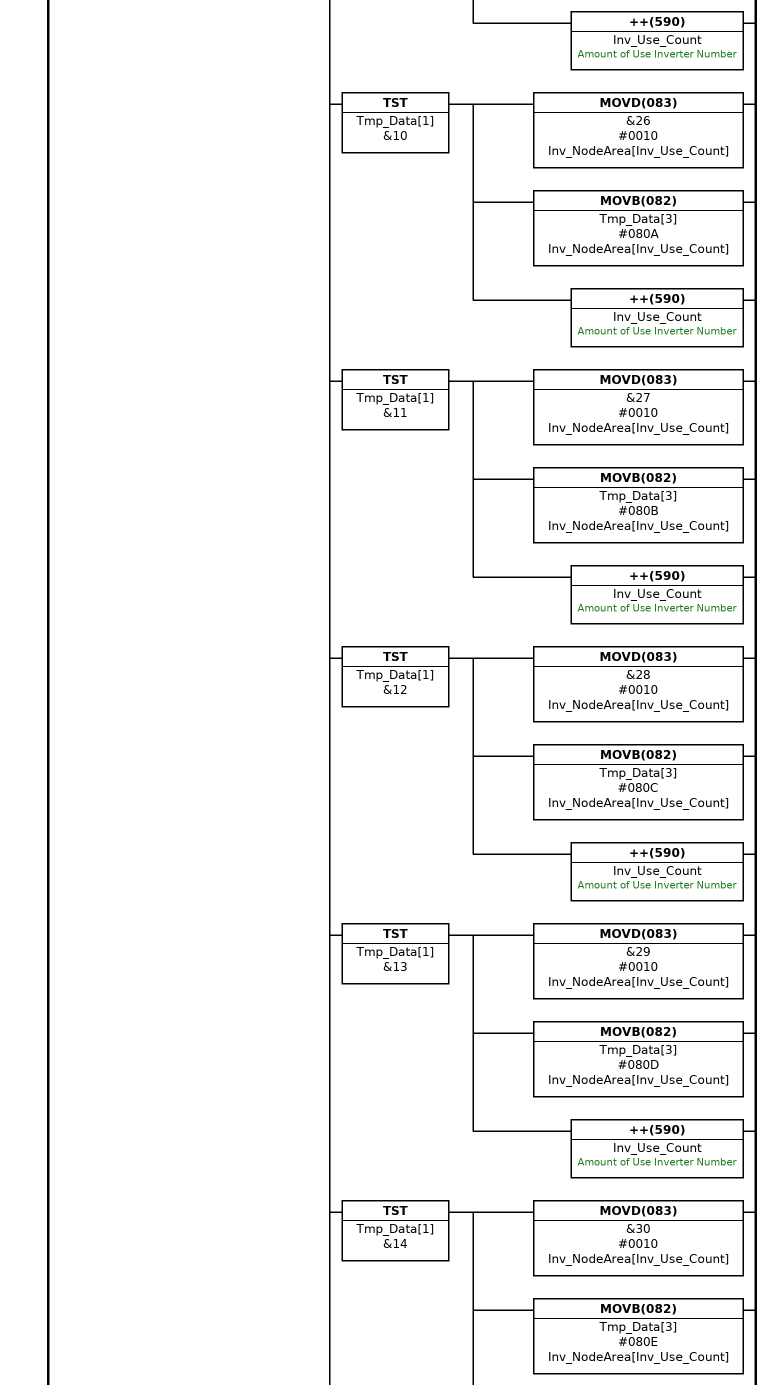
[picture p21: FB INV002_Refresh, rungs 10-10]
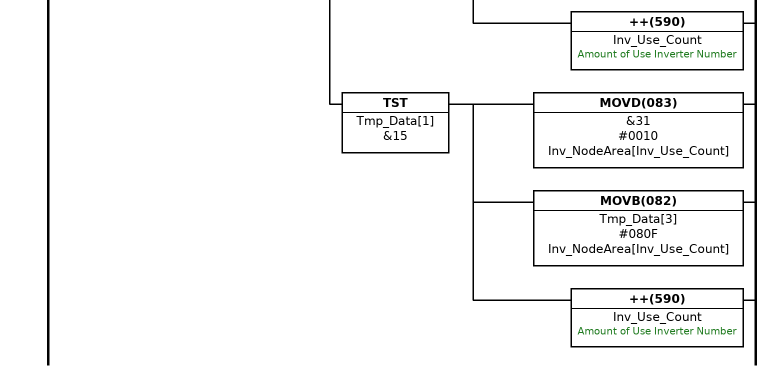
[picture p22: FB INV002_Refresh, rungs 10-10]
; rung 10: Set Applicable Axis Inverter&16 to &31
LD AddressOk_Bit  ; Addrss Range Check OK Bit
LDNOT BUSY_Run  ; Internal Processing Flag
OR Data_Change  ; Detect input data change
ANDLD
OUT TR0
ANDTST(350) Tmp_Data[1] &0
MOVD(083) &16 #0010 Inv_NodeArea[Inv_Use_Count]
MOVB(082) Tmp_Data[3] #0800 Inv_NodeArea[Inv_Use_Count]
++(590) Inv_Use_Count  ; Amount of Use Inverter Number
LD TR0
ANDTST(350) Tmp_Data[1] &1
MOVD(083) &17 #0010 Inv_NodeArea[Inv_Use_Count]
MOVB(082) Tmp_Data[3] #0801 Inv_NodeArea[Inv_Use_Count]
++(590) Inv_Use_Count  ; Amount of Use Inverter Number
LD TR0
ANDTST(350) Tmp_Data[1] &2
MOVD(083) &18 #0010 Inv_NodeArea[Inv_Use_Count]
MOVB(082) Tmp_Data[3] #0802 Inv_NodeArea[Inv_Use_Count]
++(590) Inv_Use_Count  ; Amount of Use Inverter Number
LD TR0
ANDTST(350) Tmp_Data[1] &3
MOVD(083) &19 #0010 Inv_NodeArea[Inv_Use_Count]
MOVB(082) Tmp_Data[3] #0803 Inv_NodeArea[Inv_Use_Count]
++(590) Inv_Use_Count  ; Amount of Use Inverter Number
LD TR0
ANDTST(350) Tmp_Data[1] &4
MOVD(083) &20 #0010 Inv_NodeArea[Inv_Use_Count]
MOVB(082) Tmp_Data[3] #0804 Inv_NodeArea[Inv_Use_Count]
++(590) Inv_Use_Count  ; Amount of Use Inverter Number
LD TR0
ANDTST(350) Tmp_Data[1] &5
MOVD(083) &21 #0010 Inv_NodeArea[Inv_Use_Count]
MOVB(082) Tmp_Data[3] #0805 Inv_NodeArea[Inv_Use_Count]
++(590) Inv_Use_Count  ; Amount of Use Inverter Number
LD TR0
ANDTST(350) Tmp_Data[1] &6
MOVD(083) &22 #0010 Inv_NodeArea[Inv_Use_Count]
MOVB(082) Tmp_Data[3] #0806 Inv_NodeArea[Inv_Use_Count]
++(590) Inv_Use_Count  ; Amount of Use Inverter Number
LD TR0
ANDTST(350) Tmp_Data[1] &7
MOVD(083) &23 #0010 Inv_NodeArea[Inv_Use_Count]
MOVB(082) Tmp_Data[3] #0807 Inv_NodeArea[Inv_Use_Count]
++(590) Inv_Use_Count  ; Amount of Use Inverter Number
LD TR0
ANDTST(350) Tmp_Data[1] &8
MOVD(083) &24 #0010 Inv_NodeArea[Inv_Use_Count]
MOVB(082) Tmp_Data[3] #0808 Inv_NodeArea[Inv_Use_Count]
++(590) Inv_Use_Count  ; Amount of Use Inverter Number
LD TR0
ANDTST(350) Tmp_Data[1] &9
MOVD(083) &25 #0010 Inv_NodeArea[Inv_Use_Count]
MOVB(082) Tmp_Data[3] #0809 Inv_NodeArea[Inv_Use_Count]
++(590) Inv_Use_Count  ; Amount of Use Inverter Number
LD TR0
ANDTST(350) Tmp_Data[1] &10
MOVD(083) &26 #0010 Inv_NodeArea[Inv_Use_Count]
MOVB(082) Tmp_Data[3] #080A Inv_NodeArea[Inv_Use_Count]
++(590) Inv_Use_Count  ; Amount of Use Inverter Number
LD TR0
ANDTST(350) Tmp_Data[1] &11
MOVD(083) &27 #0010 Inv_NodeArea[Inv_Use_Count]
MOVB(082) Tmp_Data[3] #080B Inv_NodeArea[Inv_Use_Count]
++(590) Inv_Use_Count  ; Amount of Use Inverter Number
LD TR0
ANDTST(350) Tmp_Data[1] &12
MOVD(083) &28 #0010 Inv_NodeArea[Inv_Use_Count]
MOVB(082) Tmp_Data[3] #080C Inv_NodeArea[Inv_Use_Count]
++(590) Inv_Use_Count  ; Amount of Use Inverter Number
LD TR0
ANDTST(350) Tmp_Data[1] &13
MOVD(083) &29 #0010 Inv_NodeArea[Inv_Use_Count]
MOVB(082) Tmp_Data[3] #080D Inv_NodeArea[Inv_Use_Count]
++(590) Inv_Use_Count  ; Amount of Use Inverter Number
LD TR0
ANDTST(350) Tmp_Data[1] &14
MOVD(083) &30 #0010 Inv_NodeArea[Inv_Use_Count]
MOVB(082) Tmp_Data[3] #080E Inv_NodeArea[Inv_Use_Count]
++(590) Inv_Use_Count  ; Amount of Use Inverter Number
LD TR0
ANDTST(350) Tmp_Data[1] &15
MOVD(083) &31 #0010 Inv_NodeArea[Inv_Use_Count]
MOVB(082) Tmp_Data[3] #080F Inv_NodeArea[Inv_Use_Count]
++(590) Inv_Use_Count  ; Amount of Use Inverter Number

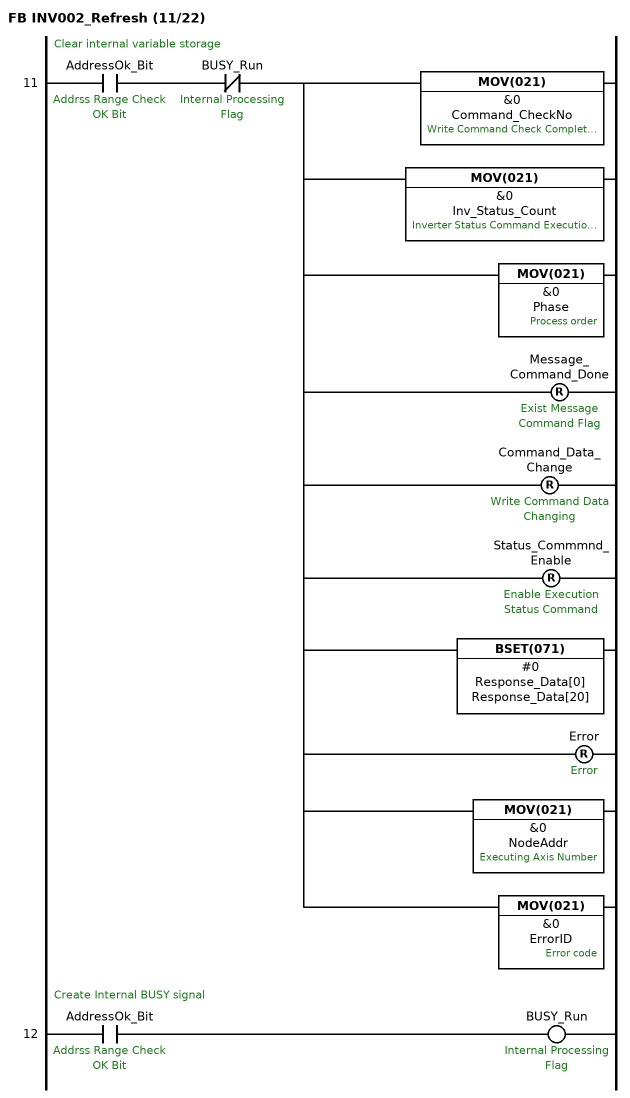
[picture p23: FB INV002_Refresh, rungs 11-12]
; rung 11: Clear internal variable storage
LD AddressOk_Bit  ; Addrss Range Check OK Bit
ANDNOT BUSY_Run  ; Internal Processing Flag
MOV(021) &0 Command_CheckNo  ; Write Command Check Complete Number
MOV(021) &0 Inv_Status_Count  ; Inverter Status Command Execution Number
MOV(021) &0 Phase  ; Process order
RSET Message_Command_Done  ; Exist Message Command Flag
RSET Command_Data_Change  ; Write Command Data Changing
RSET Status_Commmnd_Enable  ; Enable Execution Status Command
BSET(071) #0 Response_Data[0] Response_Data[20]
RSET Error  ; Error
MOV(021) &0 NodeAddr  ; Executing Axis Number
MOV(021) &0 ErrorID  ; Error code
; rung 12: Create Internal BUSY signal
LD AddressOk_Bit  ; Addrss Range Check OK Bit
OUT BUSY_Run  ; Internal Processing Flag

; rung 13: Message Command Data checks existence of Send
LD AddressOk_Bit  ; Addrss Range Check OK Bit
AND BUSY_Run  ; Internal Processing Flag
AND=(300) &0 Phase  ; Process order
AND=(300) #1 +1^IR1
SET Message_Command_Done  ; Exist Message Command Flag
MOV(021) &1 Phase  ; Process order





; rung 14: Write Command Checks Existence of Changing / Inverter Number&1 to &16
LD AddressOk_Bit  ; Addrss Range Check OK Bit
AND BUSY_Run  ; Internal Processing Flag
ANDNOT Message_Command_Done  ; Exist Message Command Flag
AND=(300) &0 Phase  ; Process order
ANDNOT Status_Commmnd_INT  ; Status Interrupt Flag
OUT TR0
MOVL(498) Scanlist Tmp_Data[2]  ; Scanlist
ANDTST(350) Tmp_Data[2] &1
AND>(320) &1 Command_CheckNo  ; Write Command Check Complete Number
ANDL(610) ^IR0 #FFFF0007 Tmp_Data[0]
AND<>L(306) Tmp_Data[0] Last_Area_Status[0]
SET Command_Data_Change  ; Write Command Data Changing
MOV(021) &1 Command_CheckNo  ; Write Command Check Complete Number
LD TR0
ANDNOT Command_Data_Change  ; Write Command Data Changing
ANDTST(350) Tmp_Data[2] &2
AND>(320) &2 Command_CheckNo  ; Write Command Check Complete Number
ANDL(610) +2^IR0 #FFFF0007 Tmp_Data[0]
AND<>L(306) Tmp_Data[0] Last_Area_Status[2]
SET Command_Data_Change  ; Write Command Data Changing
MOV(021) &2 Command_CheckNo  ; Write Command Check Complete Number
LD TR0
ANDNOT Command_Data_Change  ; Write Command Data Changing
ANDTST(350) Tmp_Data[2] &3
AND>(320) &3 Command_CheckNo  ; Write Command Check Complete Number
ANDL(610) +4^IR0 #FFFF0007 Tmp_Data[0]
AND<>L(306) Tmp_Data[0] Last_Area_Status[4]
SET Command_Data_Change  ; Write Command Data Changing
MOV(021) &3 Command_CheckNo  ; Write Command Check Complete Number
LD TR0
ANDNOT Command_Data_Change  ; Write Command Data Changing
ANDTST(350) Tmp_Data[2] &4
AND>(320) &4 Command_CheckNo  ; Write Command Check Complete Number
ANDL(610) +6^IR0 #FFFF0007 Tmp_Data[0]
AND<>L(306) Tmp_Data[0] Last_Area_Status[6]
SET Command_Data_Change  ; Write Command Data Changing
MOV(021) &4 Command_CheckNo  ; Write Command Check Complete Number
LD TR0
ANDNOT Command_Data_Change  ; Write Command Data Changing
ANDTST(350) Tmp_Data[2] &5
AND>(320) &5 Command_CheckNo  ; Write Command Check Complete Number
ANDL(610) +8^IR0 #FFFF0007 Tmp_Data[0]
AND<>L(306) Tmp_Data[0] Last_Area_Status[8]
SET Command_Data_Change  ; Write Command Data Changing
MOV(021) &5 Command_CheckNo  ; Write Command Check Complete Number
LD TR0
ANDNOT Command_Data_Change  ; Write Command Data Changing
ANDTST(350) Tmp_Data[2] &6
AND>(320) &6 Command_CheckNo  ; Write Command Check Complete Number
ANDL(610) +10^IR0 #FFFF0007 Tmp_Data[0]
AND<>L(306) Tmp_Data[0] Last_Area_Status[10]
SET Command_Data_Change  ; Write Command Data Changing
MOV(021) &6 Command_CheckNo  ; Write Command Check Complete Number
LD TR0
ANDNOT Command_Data_Change  ; Write Command Data Changing
ANDTST(350) Tmp_Data[2] &7
AND>(320) &7 Command_CheckNo  ; Write Command Check Complete Number
ANDL(610) +12^IR0 #FFFF0007 Tmp_Data[0]
AND<>L(306) Tmp_Data[0] Last_Area_Status[12]
SET Command_Data_Change  ; Write Command Data Changing
MOV(021) &7 Command_CheckNo  ; Write Command Check Complete Number
LD TR0
ANDNOT Command_Data_Change  ; Write Command Data Changing
ANDTST(350) Tmp_Data[2] &8
AND>(320) &8 Command_CheckNo  ; Write Command Check Complete Number
ANDL(610) +14^IR0 #FFFF0007 Tmp_Data[0]
AND<>L(306) Tmp_Data[0] Last_Area_Status[14]
SET Command_Data_Change  ; Write Command Data Changing
MOV(021) &8 Command_CheckNo  ; Write Command Check Complete Number
LD TR0
ANDNOT Command_Data_Change  ; Write Command Data Changing
ANDTST(350) Tmp_Data[2] &9
AND>(320) &9 Command_CheckNo  ; Write Command Check Complete Number
ANDL(610) +16^IR0 #FFFF0007 Tmp_Data[0]
AND<>L(306) Tmp_Data[0] Last_Area_Status[16]
SET Command_Data_Change  ; Write Command Data Changing
MOV(021) &9 Command_CheckNo  ; Write Command Check Complete Number
LD TR0
ANDNOT Command_Data_Change  ; Write Command Data Changing
ANDTST(350) Tmp_Data[2] &10
AND>(320) &10 Command_CheckNo  ; Write Command Check Complete Number
ANDL(610) +18^IR0 #FFFF0007 Tmp_Data[0]
AND<>L(306) Tmp_Data[0] Last_Area_Status[18]
SET Command_Data_Change  ; Write Command Data Changing
MOV(021) &10 Command_CheckNo  ; Write Command Check Complete Number
LD TR0
ANDNOT Command_Data_Change  ; Write Command Data Changing
ANDTST(350) Tmp_Data[2] &11
AND>(320) &11 Command_CheckNo  ; Write Command Check Complete Number
ANDL(610) +20^IR0 #FFFF0007 Tmp_Data[0]
AND<>L(306) Tmp_Data[0] Last_Area_Status[20]
SET Command_Data_Change  ; Write Command Data Changing
MOV(021) &11 Command_CheckNo  ; Write Command Check Complete Number
LD TR0
ANDNOT Command_Data_Change  ; Write Command Data Changing
ANDTST(350) Tmp_Data[2] &12
AND>(320) &12 Command_CheckNo  ; Write Command Check Complete Number
ANDL(610) +22^IR0 #FFFF0007 Tmp_Data[0]
AND<>L(306) Tmp_Data[0] Last_Area_Status[22]
SET Command_Data_Change  ; Write Command Data Changing
MOV(021) &12 Command_CheckNo  ; Write Command Check Complete Number
LD TR0
ANDNOT Command_Data_Change  ; Write Command Data Changing
ANDTST(350) Tmp_Data[2] &13
AND>(320) &13 Command_CheckNo  ; Write Command Check Complete Number
ANDL(610) +24^IR0 #FFFF0007 Tmp_Data[0]
AND<>L(306) Tmp_Data[0] Last_Area_Status[24]
SET Command_Data_Change  ; Write Command Data Changing
MOV(021) &13 Command_CheckNo  ; Write Command Check Complete Number
LD TR0
ANDNOT Command_Data_Change  ; Write Command Data Changing
ANDTST(350) Tmp_Data[2] &14
AND>(320) &14 Command_CheckNo  ; Write Command Check Complete Number
ANDL(610) +26^IR0 #FFFF0007 Tmp_Data[0]
AND<>L(306) Tmp_Data[0] Last_Area_Status[26]
SET Command_Data_Change  ; Write Command Data Changing
MOV(021) &14 Command_CheckNo  ; Write Command Check Complete Number
LD TR0
ANDNOT Command_Data_Change  ; Write Command Data Changing
ANDTST(350) Tmp_Data[2] &15
AND>(320) &15 Command_CheckNo  ; Write Command Check Complete Number
ANDL(610) +28^IR0 #FFFF0007 Tmp_Data[0]
AND<>L(306) Tmp_Data[0] Last_Area_Status[28]
SET Command_Data_Change  ; Write Command Data Changing
MOV(021) &15 Command_CheckNo  ; Write Command Check Complete Number
LD TR0
ANDNOT Command_Data_Change  ; Write Command Data Changing
ANDTST(350) Tmp_Data[3] &0
AND>(320) &16 Command_CheckNo  ; Write Command Check Complete Number
ANDL(610) +30^IR0 #FFFF0007 Tmp_Data[0]
AND<>L(306) Tmp_Data[0] Last_Area_Status[30]
SET Command_Data_Change  ; Write Command Data Changing
MOV(021) &16 Command_CheckNo  ; Write Command Check Complete Number





; rung 15: Write Command Checks Existence of Changing / Inverter Number&17 to &31
LD AddressOk_Bit  ; Addrss Range Check OK Bit
AND BUSY_Run  ; Internal Processing Flag
ANDNOT Message_Command_Done  ; Exist Message Command Flag
AND=(300) &0 Phase  ; Process order
ANDNOT Status_Commmnd_INT  ; Status Interrupt Flag
OUT TR0
ANDNOT Command_Data_Change  ; Write Command Data Changing
ANDTST(350) Tmp_Data[3] &1
AND>(320) &17 Command_CheckNo  ; Write Command Check Complete Number
ANDL(610) +32^IR0 #FFFF0007 Tmp_Data[0]
AND<>L(306) Tmp_Data[0] Last_Area_Status[32]
SET Command_Data_Change  ; Write Command Data Changing
MOV(021) &17 Command_CheckNo  ; Write Command Check Complete Number
LD TR0
ANDNOT Command_Data_Change  ; Write Command Data Changing
ANDTST(350) Tmp_Data[3] &2
AND>(320) &18 Command_CheckNo  ; Write Command Check Complete Number
ANDL(610) +34^IR0 #FFFF0007 Tmp_Data[0]
AND<>L(306) Tmp_Data[0] Last_Area_Status[34]
SET Command_Data_Change  ; Write Command Data Changing
MOV(021) &18 Command_CheckNo  ; Write Command Check Complete Number
LD TR0
ANDNOT Command_Data_Change  ; Write Command Data Changing
ANDTST(350) Tmp_Data[3] &3
AND>(320) &19 Command_CheckNo  ; Write Command Check Complete Number
ANDL(610) +36^IR0 #FFFF0007 Tmp_Data[0]
AND<>L(306) Tmp_Data[0] Last_Area_Status[36]
SET Command_Data_Change  ; Write Command Data Changing
MOV(021) &19 Command_CheckNo  ; Write Command Check Complete Number
LD TR0
ANDNOT Command_Data_Change  ; Write Command Data Changing
ANDTST(350) Tmp_Data[3] &4
AND>(320) &20 Command_CheckNo  ; Write Command Check Complete Number
ANDL(610) +38^IR0 #FFFF0007 Tmp_Data[0]
AND<>L(306) Tmp_Data[0] Last_Area_Status[38]
SET Command_Data_Change  ; Write Command Data Changing
MOV(021) &20 Command_CheckNo  ; Write Command Check Complete Number
LD TR0
ANDNOT Command_Data_Change  ; Write Command Data Changing
ANDTST(350) Tmp_Data[3] &5
AND>(320) &21 Command_CheckNo  ; Write Command Check Complete Number
ANDL(610) +40^IR0 #FFFF0007 Tmp_Data[0]
AND<>L(306) Tmp_Data[0] Last_Area_Status[40]
SET Command_Data_Change  ; Write Command Data Changing
MOV(021) &21 Command_CheckNo  ; Write Command Check Complete Number
LD TR0
ANDNOT Command_Data_Change  ; Write Command Data Changing
ANDTST(350) Tmp_Data[3] &6
AND>(320) &22 Command_CheckNo  ; Write Command Check Complete Number
ANDL(610) +42^IR0 #FFFF0007 Tmp_Data[0]
AND<>L(306) Tmp_Data[0] Last_Area_Status[42]
SET Command_Data_Change  ; Write Command Data Changing
MOV(021) &22 Command_CheckNo  ; Write Command Check Complete Number
LD TR0
ANDNOT Command_Data_Change  ; Write Command Data Changing
ANDTST(350) Tmp_Data[3] &7
AND>(320) &23 Command_CheckNo  ; Write Command Check Complete Number
ANDL(610) +44^IR0 #FFFF0007 Tmp_Data[0]
AND<>L(306) Tmp_Data[0] Last_Area_Status[44]
SET Command_Data_Change  ; Write Command Data Changing
MOV(021) &23 Command_CheckNo  ; Write Command Check Complete Number
LD TR0
ANDNOT Command_Data_Change  ; Write Command Data Changing
ANDTST(350) Tmp_Data[3] &8
AND>(320) &24 Command_CheckNo  ; Write Command Check Complete Number
ANDL(610) +46^IR0 #FFFF0007 Tmp_Data[0]
AND<>L(306) Tmp_Data[0] Last_Area_Status[46]
SET Command_Data_Change  ; Write Command Data Changing
MOV(021) &24 Command_CheckNo  ; Write Command Check Complete Number
LD TR0
ANDNOT Command_Data_Change  ; Write Command Data Changing
ANDTST(350) Tmp_Data[3] &9
AND>(320) &25 Command_CheckNo  ; Write Command Check Complete Number
ANDL(610) +48^IR0 #FFFF0007 Tmp_Data[0]
AND<>L(306) Tmp_Data[0] Last_Area_Status[48]
SET Command_Data_Change  ; Write Command Data Changing
MOV(021) &25 Command_CheckNo  ; Write Command Check Complete Number
LD TR0
ANDNOT Command_Data_Change  ; Write Command Data Changing
ANDTST(350) Tmp_Data[3] &10
AND>(320) &26 Command_CheckNo  ; Write Command Check Complete Number
ANDL(610) +50^IR0 #FFFF0007 Tmp_Data[0]
AND<>L(306) Tmp_Data[0] Last_Area_Status[50]
SET Command_Data_Change  ; Write Command Data Changing
MOV(021) &26 Command_CheckNo  ; Write Command Check Complete Number
LD TR0
ANDNOT Command_Data_Change  ; Write Command Data Changing
ANDTST(350) Tmp_Data[3] &11
AND>(320) &27 Command_CheckNo  ; Write Command Check Complete Number
ANDL(610) +52^IR0 #FFFF0007 Tmp_Data[0]
AND<>L(306) Tmp_Data[0] Last_Area_Status[52]
SET Command_Data_Change  ; Write Command Data Changing
MOV(021) &27 Command_CheckNo  ; Write Command Check Complete Number
LD TR0
ANDNOT Command_Data_Change  ; Write Command Data Changing
ANDTST(350) Tmp_Data[3] &12
AND>(320) &28 Command_CheckNo  ; Write Command Check Complete Number
ANDL(610) +54^IR0 #FFFF0007 Tmp_Data[0]
AND<>L(306) Tmp_Data[0] Last_Area_Status[54]
SET Command_Data_Change  ; Write Command Data Changing
MOV(021) &28 Command_CheckNo  ; Write Command Check Complete Number
LD TR0
ANDNOT Command_Data_Change  ; Write Command Data Changing
ANDTST(350) Tmp_Data[3] &13
AND>(320) &29 Command_CheckNo  ; Write Command Check Complete Number
ANDL(610) +56^IR0 #FFFF0007 Tmp_Data[0]
AND<>L(306) Tmp_Data[0] Last_Area_Status[56]
SET Command_Data_Change  ; Write Command Data Changing
MOV(021) &29 Command_CheckNo  ; Write Command Check Complete Number
LD TR0
ANDNOT Command_Data_Change  ; Write Command Data Changing
ANDTST(350) Tmp_Data[3] &14
AND>(320) &30 Command_CheckNo  ; Write Command Check Complete Number
ANDL(610) +58^IR0 #FFFF0007 Tmp_Data[0]
AND<>L(306) Tmp_Data[0] Last_Area_Status[58]
SET Command_Data_Change  ; Write Command Data Changing
MOV(021) &30 Command_CheckNo  ; Write Command Check Complete Number
LD TR0
ANDNOT Command_Data_Change  ; Write Command Data Changing
ANDTST(350) Tmp_Data[3] &15
AND>(320) &31 Command_CheckNo  ; Write Command Check Complete Number
ANDL(610) +60^IR0 #FFFF0007 Tmp_Data[0]
AND<>L(306) Tmp_Data[0] Last_Area_Status[60]
SET Command_Data_Change  ; Write Command Data Changing
MOV(021) &31 Command_CheckNo  ; Write Command Check Complete Number
LD TR0
AND Command_Data_Change  ; Write Command Data Changing
OUT TR1
MOV(021) Command_CheckNo Inv_Command_Change_Position  ; Write Command Check Complete Number, Inverter Write Command Changing Position
-(410) Inv_Command_Change_Position &1 Tmp_Data[0]  ; Inverter Write Command Changing Position
*(420) Tmp_Data[0] &2 Offset  ; For Address Culcurate
+L(401) IR0 Offset IR3  ; For Address Culcurate
ANDL(610) ^IR3 #FFFF0007 Directive_Data[0]
-(410) Inv_Use_Count &1 No  ; Amount of Use Inverter Number, MatrixNo
MOV(021) &0 Tmp_Data[0]
MOVD(083) Inv_NodeArea[No] #0010 Tmp_Data[0]
AND<=(315) Tmp_Data[0] Command_CheckNo  ; Write Command Check Complete Number
SET Status_Commmnd_INT  ; Status Interrupt Flag
MOV(021) &0 Command_CheckNo  ; Write Command Check Complete Number
LD TR1
MOV(021) &1 Phase  ; Process order
LD TR0
ANDNOT Command_Data_Change  ; Write Command Data Changing
MOV(021) &0 Command_CheckNo  ; Write Command Check Complete Number

; rung 16: Check Status Command / For Status Get Inverter Model and Number
LD AddressOk_Bit  ; Addrss Range Check OK Bit
AND BUSY_Run  ; Internal Processing Flag
ANDNOT Message_Command_Done  ; Exist Message Command Flag
ANDNOT Command_Data_Change  ; Write Command Data Changing
AND=(300) &0 Phase  ; Process order
OUT TR0
AND>=(325) Inv_Use_Count Inv_Status_Count  ; Amount of Use Inverter Number, Inverter Status Command Execution Number
++(590) Inv_Status_Count  ; Inverter Status Command Execution Number
LD TR0
AND<(310) Inv_Use_Count Inv_Status_Count  ; Amount of Use Inverter Number, Inverter Status Command Execution Number
MOV(021) &1 Inv_Status_Count  ; Inverter Status Command Execution Number
LD TR0
-(410) Inv_Status_Count &1 No  ; Inverter Status Command Execution Number, MatrixNo
MOV(021) Inv_NodeArea[No] Status_Inv_No  ; Status Command Slave Number
SET Status_Commmnd_Enable  ; Enable Execution Status Command
MOV(021) &1 Phase  ; Process order


; rung 17: Create CMND control data
LD AddressOk_Bit  ; Addrss Range Check OK Bit
AND BUSY_Run  ; Internal Processing Flag
AND=(300) &1 Phase  ; Process order
OUT TR0
MOVL(498) &0 Control_Data[0]
AND Message_Command_Done  ; Exist Message Command Flag
MOVD(083) +23^IR1 #0012 Control_Data[0]
MOVD(083) +23^IR1 #0010 Control_Data[1]
LD TR0
AND Command_Data_Change  ; Write Command Data Changing
MOV(021) &13 Control_Data[0]
MOV(021) &10 Control_Data[1]
LD TR0
AND Status_Commmnd_Enable  ; Enable Execution Status Command
MOV(021) &8 Control_Data[0]
MOV(021) &9 Control_Data[1]
LD TR0
MOV(021) #0 Control_Data[2]
MOVD(083) #0 #0210 Control_Data[3]
AND=(300) #BBBB UnitSelect_Tmp  ; SCB/Select SCU Bit storage(internal variables)
-(410) PortNo_Tmp &1 Tmp_Data[0]  ; Serial port No. storage(internal variables)
+(400) #E4 Tmp_Data[0] Tmp_Data[0]
MOVD(083) Tmp_Data[0] #0010 Control_Data[3]
LD TR0
AND=(300) #CCCC UnitSelect_Tmp  ; SCB/Select SCU Bit storage(internal variables)
-(410) PortNo_Tmp &1 Tmp_Data[0]  ; Serial port No. storage(internal variables)
-(410) #FD Tmp_Data[0] Tmp_Data[0]
MOVD(083) Tmp_Data[0] #0010 Control_Data[3]
LD TR0
AND<>(305) #BBBB UnitSelect_Tmp  ; SCB/Select SCU Bit storage(internal variables)
AND<>(305) #CCCC UnitSelect_Tmp  ; SCB/Select SCU Bit storage(internal variables)
*(420) &4 UnitSelect_Tmp Offset  ; SCB/Select SCU Bit storage(internal variables), For Address Culcurate
+L(401) Offset #80 Offset  ; For Address Culcurate
-(410) PortNo_Tmp &1 Tmp_Data[0]  ; Serial port No. storage(internal variables)
+L(401) Offset Tmp_Data[0] Offset  ; For Address Culcurate
MOVD(083) Offset #0010 Control_Data[3]  ; For Address Culcurate
LD TR0
MOV(021) P_ComPort_Retry Control_Data[4]  ; FB Communications command retry count
MOV(021) P_ComPort_WatchResTime Control_Data[5]  ; FB Communications command response Monitor time



; rung 18: Execute CMND
LD AddressOk_Bit  ; Addrss Range Check OK Bit
AND BUSY_Run  ; Internal Processing Flag
AND P_ComPort_AutoAlloc_Available  ; Auto allocation avarable bit
AND=(300) &1 Phase  ; Process order
OUT TR0
BSET(071) #0 Command_Data[0] Command_Data[21]
MOV(021) #2804 Command_Data[0]
AND Message_Command_Done  ; Exist Message Command Flag
XFER(070) &21 +24^IR1 Command_Data[1]
LD TR0
AND Command_Data_Change  ; Write Command Data Changing
OUT TR1
MOVD(083) Inv_Command_Change_Position #0210 Command_Data[1]  ; Inverter Write Command Changing Position
MOVD(083) #10 #0010 Command_Data[1]
MOV(021) #0001 Command_Data[2]
MOV(021) #0002 Command_Data[3]
MOVD(083) #04 #0210 Command_Data[4]
MOVD(083) Directive_Data[0] #0012 Command_Data[4]
+(400) Inv_Command_Change_Position &1 Tmp_Data[1]  ; Inverter Write Command Changing Position
MOVL(498) ModelTypeMV Tmp_Data[2]  ; MV/RV Classification
NSRL(583) Tmp_Data[2] Tmp_Data[1]
ANDNOT P_CY
OUT TR2
LDTST(350) Directive_Data[0] &0
ORTST(350) Directive_Data[0] &1
ANDLD
SETB(532) Command_Data[5] &8
LD TR2
ANDTSTN(351) Directive_Data[0] &0
ANDTSTN(351) Directive_Data[0] &1
RSTB(533) Command_Data[5] &8
LD TR2
ANDTST(350) Directive_Data[0] &1
SETB(532) Command_Data[5] &9
LD TR2
ANDTSTN(351) Directive_Data[0] &1
RSTB(533) Command_Data[5] &9
LD TR1
AND P_CY
MOVB(082) Directive_Data[0] #0800 Command_Data[5]
MOVB(082) Directive_Data[0] #0901 Command_Data[5]
LD TR1
ANDTST(350) Directive_Data[0] &2
SETB(532) Command_Data[5] &11
LD TR1
ANDTSTN(351) Directive_Data[0] &2
RSTB(533) Command_Data[5] &11
LD TR1
MOVD(083) Directive_Data[1] #0012 Command_Data[5]
MOVD(083) Directive_Data[1] #0210 Command_Data[6]
LD TR0
AND Status_Commmnd_Enable  ; Enable Execution Status Command
MOVD(083) Status_Inv_No #0210 Command_Data[1]  ; Status Command Slave Number
MOVD(083) #03 #0010 Command_Data[1]
MOV(021) #002C Command_Data[2]
MOV(021) #0001 Command_Data[3]
LD TR0
CMND(490) Command_Data[0] Response_Data[0] Control_Data[0]
AND P_ER
OUT P_Error  ; Error Bit
LD TR0
OUT WAIT  ; First Cycle Wait Bit
MOV(021) P_ComPort_AllocatedNumber CMNDPort  ; Network port No., Port Number 1(Automatic Setting)
MOV(021) &2 Phase  ; Process order


; rung 19: Check CMND Response Data and Transfer Response Area
LD AddressOk_Bit  ; Addrss Range Check OK Bit
AND BUSY_Run  ; Internal Processing Flag
ANDNOT WAIT  ; First Cycle Wait Bit
LDTST(350) P_ComPort_Finished0_7 CMNDPort  ; Communications Complete Cycle Bit, Port Number 1(Automatic Setting)
ORTST(350) P_ComPort_Error CMNDPort  ; Communication Port No. 0 to 7 Error Bit, Port Number 1(Automatic Setting)
ANDLD
AND=(300) &2 Phase  ; Process order
OUT TR0
XFER(070) &21 Response_Data[0] Tmp_Data[0]
ANDW(034) Response_Data[1] #7F3F Tmp_Data[1]
XFER(070) &21 Tmp_Data[0] +2^IR1
LD<>(305) #2804 Response_Data[0]
OR<>(305) &0 Tmp_Data[1]
ANDLD
OUT Response_CodeNG  ; Response end code error
MOV(021) Response_Data[1] ErrorID  ; Error code
MOV(021) &0 Tmp_Data[0]
MOVD(083) ErrorID #0003 Tmp_Data[0]  ; Error code
AND=(300) &1 Tmp_Data[0]
OUT Error_Skip  ; Fatal Error Skip Flag
LD TR0
ANDNOT Response_CodeNG  ; Response end code error
OUT TR1
ANDW(034) Response_Data[2] #00FF Tmp_Data[0]
MOVD(083) Response_Data[2] #0012 Tmp_Data[1]
ANDW(034) Tmp_Data[1] #00FF Tmp_Data[1]
MOVD(083) Command_Data[1] #0012 Tmp_Data[2]
ANDW(034) Tmp_Data[2] #00FF Tmp_Data[2]
LD=(300) #83 Tmp_Data[0]
OR<>(305) Tmp_Data[1] Tmp_Data[2]
ANDLD
OUT Response_NG  ; Response error
MOVD(083) Response_Data[3] #0012 ErrorID  ; Error code
LD TR1
ANDNOT Response_NG  ; Response error
OUT TR2
AND Command_Data_Change  ; Write Command Data Changing
-(410) Inv_Command_Change_Position &1 Tmp_Data[0]  ; Inverter Write Command Changing Position
*(420) Tmp_Data[0] &2 Offset  ; For Address Culcurate
MOVL(498) Directive_Data[0] Last_Area_Status[Offset]
LD TR2
AND Status_Commmnd_Enable  ; Enable Execution Status Command
MOVD(083) Response_Data[3] #0210 Status_2C  ; Register2C  response data
MOVD(083) Response_Data[4] #0012 Status_2C  ; Register2C  response data
LD TR0
MOV(021) &3 Phase  ; Process order
AND Message_Command_Done  ; Exist Message Command Flag
RSET Message_Command_Done  ; Exist Message Command Flag
MOV(021) &0 ^IR1
LD TR0
AND Command_Data_Change  ; Write Command Data Changing
RSET Command_Data_Change  ; Write Command Data Changing

; rung 20: Generate Status Process
LD Status_Commmnd_Enable  ; Enable Execution Status Command
ANDNOT Response_CodeNG  ; Response end code error
AND=(300) &3 Phase  ; Process order
OUT TR0
MOV(021) Status_Inv_No Tmp_Data[0]  ; Status Command Slave Number
ANDW(034) Tmp_Data[0] #00FF Tmp_Data[0]
-(410) Tmp_Data[0] &1 Tmp_Data[0]
*(420) Tmp_Data[0] &2 Tmp_Data[0]
MOV(021) Tmp_Data[0] DR0
AND>(320) #0100 Status_Inv_No  ; Status Command Slave Number
XFRB(062) #0C30 Status_2C DR0^IR0  ; Register2C  response data
MOVB(082) Status_2C #0F0E DR0^IR0  ; Register2C  response data
LD TR0
AND<=(315) #0100 Status_Inv_No  ; Status Command Slave Number
XFRB(062) #0330 Status_2C DR0^IR0  ; Register2C  response data
XFRB(062) #0374 Status_2C DR0^IR0  ; Register2C  response data
XFRB(062) #04B8 Status_2C DR0^IR0  ; Register2C  response data
MOVB(082) Status_2C #0F0E DR0^IR0  ; Register2C  response data
LD TR0
ANDTST(350) DR0^IR0 &15
OUT INV_Error  ; InverterNormal end
LD TR0
RSET Status_Commmnd_Enable  ; Enable Execution Status Command
AND Status_Commmnd_INT  ; Status Interrupt Flag
RSET Status_Commmnd_INT  ; Status Interrupt Flag

; rung 21: Executing Node Number
LD AddressOk_Bit  ; Addrss Range Check OK Bit
AND BUSY_Run  ; Internal Processing Flag
MOVD(083) Command_Data[1] #0012 NodeAddr  ; Executing Axis Number
; rung 22: Create ERROR signal
LD EN
OUT TR0
LD Response_CodeNG  ; Response end code error
OR Response_NG  ; Response error
OR P_Error  ; Error Bit
OR NG_Bit  ; Range Check NG Bit
OR INV_Error  ; InverterNormal end
ANDLD
OUT Error  ; Error
LD TR0
ANDNOT Error  ; Error
MOV(021) &0 ErrorID  ; Error code
; rung 23: CMND Command Check Communication End
LD EN
AND=(300) &3 Phase  ; Process order
OUT Command_Fin  ; CMND Transferring End

; rung 24: Interval Timer
LD EN
LD Command_Fin  ; CMND Transferring End
OR Interval_Start  ; Interval Count Start
ANDLD
ANDNOT Interval_TimeUp  ; Interval Time Up
OUT TR0
ANDNOT Interval_Start  ; Interval Count Start
OUT TR1
MOV(021) P_FreeRunningCounter_10 FreeRunningCounter_Tmp  ; 10ms free running incremental counter, 10ms free running incremental counter record
AND<>(305) &0 IntervalCount  ; Interval
+(400) IntervalCount &1 IntervalCount_Compare  ; Interval, Interval Compare Value
LD TR1
AND=(300) &0 IntervalCount  ; Interval
MOV(021) &0 IntervalCount_Compare  ; Interval Compare Value
LD TR0
OUT Interval_Start  ; Interval Count Start
-(410) P_FreeRunningCounter_10 FreeRunningCounter_Tmp Time_Value  ; 10ms free running incremental counter, 10ms free running incremental counter record, Interval Check Time Present Value
AND<=(315) IntervalCount_Compare Time_Value  ; Interval Compare Value, Interval Check Time Present Value
OUT Interval_TimeUp  ; Interval Time Up
AND Interval_TimeUp  ; Interval Time Up
MOV(021) &0 Phase  ; Process order
; rung 25: Create BUSY signal
LD AddressOk_Bit  ; Addrss Range Check OK Bit
ANDNOT Interval_TimeUp  ; Interval Time Up
OUT BUSY  ; Processing Bit 0:Transferring Complete 1:Transferring
; rung 26: Create ENO signal
LD AddressOk_Bit  ; Addrss Range Check OK Bit
OUT ENO

; rung 27: Restore IR0 to IR3 and DR0 from temporary save buffer
LD EN
MOVL(498) SaveIR[0] IR0
MOVL(498) SaveIR[1] IR1
MOVL(498) SaveIR[2] IR2
MOVL(498) SaveIR[3] IR3
MOV(021) SaveDR DR0  ; DR0

## Function block INV032_MoveVelocityHz
; <Speed Command Hz>Outputs a run signal, rotation direction, and speed to the Inverter.
VAR_INPUT
  NodeNo : INT := 1;  (* Inverter No &1 to 31 *)
  Execute : BOOL;  (* Startup *)
  Velocity : REAL;  (* Frequency +0.00 to +400.00(in increments of 0.01) *)
  Direction : INT;  (* Direction of rotation 0:Reverse rotation 1:Normal rotation *)
  AreaID : WORD := 0082;  (* Area Type *)
  AreaNo : INT;  (* Area No. *)
END_VAR
VAR_OUTPUT
  InVelocity : BOOL;  (* Speed matching *)
  CommandAborted : BOOL;  (* Forced end 1:Abort *)
  Error : BOOL;  (* Error *)
  ErrorID : WORD;  (* Error Code *)
END_VAR
VAR
  SaveIR : ARRAY[0..0] OF DINT;  (* IR0 *)
  Velocity2 : REAL;  (* Speed * 100 times *)
  Execute_ON : BOOL;  (* StartupON *)
  Ok_Bit : BOOL;  (* Range Check OK Flag *)
  Change : BOOL;  (* Setting Change Flag *)
  AddressOk_Bit : BOOL;  (* Address Range Check OK Flag *)
  NG_Bit : BOOL;  (* Range Check NG Flag *)
  END : BOOL;  (* Process end *)
  Offset : DINT;  (* For Address Calculation *)
  AreaNo_tmp : INT;  (* Area No. comparison value *)
  Direction_tmp : WORD;  (* Direction of rotation comparison value *)
  Velocity_tmp : DINT;  (* Frequency Data comparison value *)
  NodeAddr_tmp : INT;  (* Inverter No. comparison value *)
  Tmp_IR : ARRAY[0..0] OF DINT;  (* Temporary IR for internal variables *)
  Execute_OFF : BOOL;  (* StartupOFF *)
  Tmp_Data : ARRAY[0..1] OF WORD;  (* internalFor Calculation *)
  DINT : DINT;  (* DINTconversion *)
  Error_Detect : BOOL;  (* Detect Error *)
  CommandAborted_ Flag : BOOL;  (* Abort Flag *)
  P_EM_MaxNo AT A338 : INT;  (* EM bank size *)
  EM_NoCheck : INT;  (* EM bank size check area *)
  Ok_IO : BOOL;  (* Selected CIO area range OK *)
  Type_Io AT 0 : WORD;  (* I/O area start address *)
  Ok_WR : BOOL;  (* Selected WR area range OK *)
  Type_W AT W0 : WORD;  (* WR area start address *)
  Ok_HR : BOOL;  (* Selected HR area range OK *)
  Type_H AT H0 : WORD;  (* HR area start address *)
  Ok_DM : BOOL;  (* Selected DMarea range OK *)
  Type_D AT D0 : WORD;  (* DM area start address *)
  Ok_EM : BOOL;  (* Selected EM area range OK *)
  EM_No_Tmp1 : INT;  (* EM area Calculation area 1 *)
  EM_No_Tmp2 : UDINT;  (* EM area Calculation area 2 *)
  AreaID_tmp : WORD;  (* Area Type comparison value *)
  Direction_Change : BOOL;  (* Direction of rotation change *)
  Set_IR AT 0 : WORD;  (* Index register temporary setting *)
END_VAR

; rung 0: Store IR0 in temporary save buffer
LD EN
MOVL(498) IR0 SaveIR[0]



; rung 1: Check input data range / Frequency*100.0
@LD Execute_ON  ; StartupON
OR Change  ; Setting Change Flag
ANDNOT AddressOk_Bit  ; Address Range Check OK Flag
OR Direction_Change  ; Direction of rotation change
OUT TR0
*F(456) Velocity +100.0 Velocity2  ; Frequency +0.00 to +400.00(in increments of 0.01), Speed * 100 times
FIXL(451) Velocity2 DINT  ; Speed * 100 times, DINTconversion
AND<=SL(318) &0 DINT  ; DINTconversion
AND>=SL(328) &40000 DINT  ; DINTconversion
OUT Ok_Bit  ; Range Check OK Flag
LD TR0
AND Ok_Bit  ; Range Check OK Flag
AND<=(315) &1 NodeNo  ; Inverter No &1 to 31
AND>=(325) &31 NodeNo  ; Inverter No &1 to 31
OUT Ok_Bit  ; Range Check OK Flag
LD TR0
AND Ok_Bit  ; Range Check OK Flag
AND<=(315) &0 Direction  ; Direction of rotation 0:Reverse rotation 1:Normal rotation
AND>=(325) &1 Direction  ; Direction of rotation 0:Reverse rotation 1:Normal rotation
OUT Ok_Bit  ; Range Check OK Flag
LD TR0
+(400) #50 P_EM_MaxNo EM_NoCheck  ; EM bank size, EM bank size check area
MOV(021) &62 Tmp_Data[0]
AND Ok_Bit  ; Range Check OK Flag
OUT TR1
AND=(300) #B0 AreaID  ; Area Type
-(410) &6144 Tmp_Data[0] Tmp_Data[1]
AND>(320) Tmp_Data[1] AreaNo  ; Area No.
OUT Ok_IO  ; Selected CIO area range OK
LD TR1
AND=(300) #B1 AreaID  ; Area Type
-(410) &512 Tmp_Data[0] Tmp_Data[1]
AND>(320) Tmp_Data[1] AreaNo  ; Area No.
OUT Ok_WR  ; Selected WR area range OK
LD TR1
AND=(300) #B2 AreaID  ; Area Type
-(410) &512 Tmp_Data[0] Tmp_Data[1]
AND>(320) Tmp_Data[1] AreaNo  ; Area No.
OUT Ok_HR  ; Selected HR area range OK
LD TR1
AND=(300) #82 AreaID  ; Area Type
-(410) &32768 Tmp_Data[0] Tmp_Data[1]
AND>(320) Tmp_Data[1] AreaNo  ; Area No.
OUT Ok_DM  ; Selected DMarea range OK
LD TR1
AND<=(315) #50 AreaID  ; Area Type
AND>=(325) EM_NoCheck AreaID  ; EM bank size check area, Area Type
-(410) &32768 Tmp_Data[0] Tmp_Data[1]
AND>(320) Tmp_Data[1] AreaNo  ; Area No.
OUT Ok_EM  ; Selected EM area range OK
LD TR0
LD Ok_IO  ; Selected CIO area range OK
OR Ok_WR  ; Selected WR area range OK
OR Ok_HR  ; Selected HR area range OK
OR Ok_DM  ; Selected DMarea range OK
OR Ok_EM  ; Selected EM area range OK
ANDLD
OUT Ok_Bit  ; Range Check OK Flag
LD TR0
ANDNOT Ok_Bit  ; Range Check OK Flag
SET NG_Bit  ; Range Check NG Flag
LD TR0
ANDNOT Direction_Change  ; Direction of rotation change
MOV(021) NodeNo NodeAddr_tmp  ; Inverter No &1 to 31, Inverter No. comparison value
MOV(021) AreaID AreaID_tmp  ; Area Type, Area Type comparison value
MOV(021) AreaNo AreaNo_tmp  ; Area No., Area No. comparison value
LD TR0
MOV(021) Direction Direction_tmp  ; Direction of rotation 0:Reverse rotation 1:Normal rotation, Direction of rotation comparison value

; rung 2
LD Ok_Bit  ; Range Check OK Flag
OR END  ; Process end
RSET AddressOk_Bit  ; Address Range Check OK Flag
; rung 3: Index register temporary setting(IR0)
LDNOT AddressOk_Bit  ; Address Range Check OK Flag
MOVR(560) Set_IR IR0  ; Index register temporary setting

; rung 4: Pertinent axis inverter IOM area calculation / #00018000: E0_0 Address / EM is considered as absolute address specification for the common access in CS1/CJ1/CJ1M
LD Ok_Bit  ; Range Check OK Flag
OUT TR0
AND=(300) #B0 AreaID  ; Area Type
MOVR(560) Type_Io IR0  ; I/O area start address
LD TR0
AND=(300) #B1 AreaID  ; Area Type
MOVR(560) Type_W IR0  ; WR area start address
LD TR0
AND=(300) #B2 AreaID  ; Area Type
MOVR(560) Type_H IR0  ; HR area start address
LD TR0
AND=(300) #82 AreaID  ; Area Type
MOVR(560) Type_D IR0  ; DM area start address
LD TR0
AND<=(315) #50 AreaID  ; Area Type
AND>=(325) #6C AreaID  ; Area Type
MOVL(498) #00018000 IR0
-(410) AreaID #50 Tmp_Data[0]  ; Area Type
*U(422) Tmp_Data[0] #8000 Tmp_Data[0]
+L(401) IR0 Tmp_Data[0] IR0
LD TR0
BSET(071) #0 Tmp_Data[0] Tmp_Data[1]
MOV(021) AreaNo Tmp_Data[0]  ; Area No.
MOVL(498) Tmp_Data[0] Offset  ; For Address Calculation
+L(401) IR0 Offset IR0  ; For Address Calculation
-(410) NodeNo &1 Tmp_Data[0]  ; Inverter No &1 to 31
*(420) Tmp_Data[0] &2 Offset  ; For Address Calculation
+L(401) IR0 Offset IR0  ; For Address Calculation

; rung 5: Calculate IR0 addresses only first time
LD Ok_Bit  ; Range Check OK Flag
MOVL(498) IR0 Tmp_IR[0]
SET AddressOk_Bit  ; Address Range Check OK Flag
RSET NG_Bit  ; Range Check NG Flag
; rung 6: Extract temporary IR0 for internal variables
LD AddressOk_Bit  ; Address Range Check OK Flag
MOVL(498) Tmp_IR[0] IR0

; rung 7: Frequency command ON
LD AddressOk_Bit  ; Address Range Check OK Flag
OUT TR0
@LD Execute_ON  ; StartupON
OR Direction_Change  ; Direction of rotation change
ANDLD
OUT TR1
AND=(300) &0 Direction  ; Direction of rotation 0:Reverse rotation 1:Normal rotation
SETB(532) ^IR0 &0
RSTB(533) ^IR0 &1
LD TR1
AND=(300) &1 Direction  ; Direction of rotation 0:Reverse rotation 1:Normal rotation
SETB(532) ^IR0 &1
RSTB(533) ^IR0 &0
LD TR0
AND Execute_ON  ; StartupON
MOVL(498) DINT Tmp_Data[0]  ; DINTconversion
MOV(021) Tmp_Data[0] +1^IR0
LD TR0
AND Execute_OFF  ; StartupOFF
RSET Error  ; Error
MOV(021) &0 ErrorID  ; Error Code
OUT END  ; Process end

; rung 8: Create output variables
LD Execute_ON  ; StartupON
OUT TR0
LD TR0
AND AddressOk_Bit  ; Address Range Check OK Flag
OUT TR1
LD TR1
ANDTST(350) ^IR0 &5
OUT InVelocity  ; Speed matching
LD TR1
*F(456) Velocity +100.0 Velocity2  ; Frequency +0.00 to +400.00(in increments of 0.01), Speed * 100 times
LD TR1
FIXL(451) Velocity2 Velocity_tmp  ; Speed * 100 times, Frequency Data comparison value
LD TR1
AND<>L(306) DINT Velocity_tmp  ; DINTconversion, Frequency Data comparison value
LD TR1
ANDTSTN(351) ^IR0 &0
ANDTSTN(351) ^IR0 &1
ANDNOT Execute_OFF  ; StartupOFF
ORLD
OUT CommandAborted_ Flag  ; Abort Flag
LD TR1
ANDTST(350) ^IR0 &14
LD TR1
ANDTST(350) ^IR0 &15
ORLD
LD TR0
AND NG_Bit  ; Range Check NG Flag
ORLD
OUT Error_Detect  ; Detect Error
LD TR0
ANDTST(350) ^IR0 &6
LD TR0
AND Error_Detect  ; Detect Error
ORLD
OUT Error  ; Error
; rung 9: Create Abort of output variables
; cells of this rung as drawn
  row 0 col 0: LD CommandAborted_ Flag
  row 0 col 1: LD Execute
  row 0 col 2: wire
  row 0 col 3: wire
  row 0 col 4: wire
  row 0 col 5: wire
  row 0 col 6: OUT CommandAborted
  row 1 col 0: LD CommandAborted
  vertical links (row, left of col): 0,1
; rung 10: Create ENO signal
LDNOT NG_Bit  ; Range Check NG Flag
OUT ENO
; rung 11: StartupON/OFF
; cells of this rung as drawn
  row 0 col 0: LD EN
  row 0 col 1: @LD Execute
  row 0 col 2: LDNOT Execute_OFF
  row 0 col 3: wire
  row 0 col 4: wire
  row 0 col 5: wire
  row 0 col 6: OUT Execute_ON
  row 1 col 1: LD Execute_ON
  row 2 col 1: %LD Execute
  row 2 col 2: LD Execute_ON
  row 2 col 3: wire
  row 2 col 4: wire
  row 2 col 5: wire
  row 2 col 6: OUT Execute_OFF
  row 3 col 1: LD CommandAborted_ Flag
  vertical links (row, left of col): 0,1 0,2 1,1 2,1 2,2

; rung 12: Detect input data change
LD Execute_ON  ; StartupON
AND AddressOk_Bit  ; Address Range Check OK Flag
OUT TR0
LD<>(305) NodeNo NodeAddr_tmp  ; Inverter No &1 to 31, Inverter No. comparison value
OR<>(305) AreaID AreaID_tmp  ; Area Type, Area Type comparison value
OR<>(305) AreaNo AreaNo_tmp  ; Area No., Area No. comparison value
ANDLD
OUT Change  ; Setting Change Flag
LD TR0
AND<>(305) Direction Direction_tmp  ; Direction of rotation 0:Reverse rotation 1:Normal rotation, Direction of rotation comparison value
OUT Direction_Change  ; Direction of rotation change
; rung 13: Return IR0 from temporary save buffer
LD EN
MOVL(498) SaveIR[0] IR0

## Function block INV060_Stop
; <Deceleration Stop>Stops the Inverter with deceleration.
VAR_INPUT
  NodeNo : INT := 1;  (* Inverter No &1 to 31 *)
  Execute : BOOL;  (* Startup *)
  AreaID : WORD := 0082;  (* Area Type *)
  AreaNo : INT;  (* Area No. *)
END_VAR
VAR_OUTPUT
  Done : BOOL;  (* Deceleration StopCompleted *)
  Error : BOOL;  (* Error *)
  ErrorID : WORD;  (* Error Code *)
END_VAR
VAR
  SaveIR : ARRAY[0..0] OF DINT;  (* IR0 *)
  Ok_Bit : BOOL;  (* Range Check OK Flag *)
  NG_Bit : BOOL;  (* Range Check NG Flag *)
  AddressOk_Bit : BOOL;  (* Address Range Check OK Flag *)
  Execute_ON : BOOL;  (* StartupON *)
  END : BOOL;  (* Process end *)
  Offset : DINT;  (* For Address Calculation *)
  AreaNo_tmp : INT;  (* Area No. comparison value *)
  NodeAddr_tmp : INT;  (* Inverter No. comparison value *)
  Tmp_IR : ARRAY[0..0] OF DINT;  (* Temporary IR for internal variables *)
  Execute_OFF : BOOL;  (* StartupOFF *)
  INV_Stop : BOOL;  (* stopCompleted *)
  Tmp_Data : ARRAY[0..5] OF WORD;  (* internalFor Calculation *)
  Change : BOOL;  (* Setting Change Flag *)
  P_EM_MaxNo AT A338 : INT;  (* EM bank size *)
  EM_NoCheck : INT;  (* EM bank size check area *)
  Ok_IO : BOOL;  (* Selected CIO area range OK *)
  Ok_WR : BOOL;  (* Selected WR area range OK *)
  Ok_HR : BOOL;  (* Selected HR area range OK *)
  Ok_DM : BOOL;  (* Selected DMarea range OK *)
  Ok_EM : BOOL;  (* Selected EM area range OK *)
  Type_Io AT 0 : WORD;  (* I/O area start address *)
  Type_W AT W0 : WORD;  (* WR area start address *)
  Type_H AT H0 : WORD;  (* HR area start address *)
  Type_D AT D0 : WORD;  (* DM area start address *)
  EM_No_Tmp1 : INT;  (* EM area Calculation area 1 *)
  EM_No_Tmp2 : UDINT;  (* EM area Calculation area 2 *)
  AreaID_tmp : WORD;  (* Area Type comparison value *)
  Set_IR AT 0 : WORD;  (* Index register temporary setting *)
END_VAR

; rung 0: Store IR0 in temporary save buffer
LD EN
MOVL(498) IR0 SaveIR[0]


; rung 1: Check input data range
@LD Execute_ON  ; StartupON
OR Change  ; Setting Change Flag
ANDNOT AddressOk_Bit  ; Address Range Check OK Flag
OUT TR0
AND<=(315) &1 NodeNo  ; Inverter No &1 to 31
AND>=(325) &31 NodeNo  ; Inverter No &1 to 31
OUT Ok_Bit  ; Range Check OK Flag
LD TR0
+(400) #50 P_EM_MaxNo EM_NoCheck  ; EM bank size, EM bank size check area
MOV(021) &62 Tmp_Data[0]
AND Ok_Bit  ; Range Check OK Flag
OUT TR1
AND=(300) #B0 AreaID  ; Area Type
-(410) &6144 Tmp_Data[0] Tmp_Data[1]
AND>(320) Tmp_Data[1] AreaNo  ; Area No.
OUT Ok_IO  ; Selected CIO area range OK
LD TR1
AND=(300) #B1 AreaID  ; Area Type
-(410) &512 Tmp_Data[0] Tmp_Data[1]
AND>(320) Tmp_Data[1] AreaNo  ; Area No.
OUT Ok_WR  ; Selected WR area range OK
LD TR1
AND=(300) #B2 AreaID  ; Area Type
-(410) &512 Tmp_Data[0] Tmp_Data[1]
AND>(320) Tmp_Data[1] AreaNo  ; Area No.
OUT Ok_HR  ; Selected HR area range OK
LD TR1
AND=(300) #82 AreaID  ; Area Type
-(410) &32768 Tmp_Data[0] Tmp_Data[1]
AND>(320) Tmp_Data[1] AreaNo  ; Area No.
OUT Ok_DM  ; Selected DMarea range OK
LD TR1
AND<=(315) #50 AreaID  ; Area Type
AND>=(325) EM_NoCheck AreaID  ; EM bank size check area, Area Type
-(410) &32768 Tmp_Data[0] Tmp_Data[1]
AND>(320) Tmp_Data[1] AreaNo  ; Area No.
OUT Ok_EM  ; Selected EM area range OK
LD TR0
LD Ok_IO  ; Selected CIO area range OK
OR Ok_WR  ; Selected WR area range OK
OR Ok_HR  ; Selected HR area range OK
OR Ok_DM  ; Selected DMarea range OK
OR Ok_EM  ; Selected EM area range OK
ANDLD
OUT Ok_Bit  ; Range Check OK Flag
LD TR0
ANDNOT Ok_Bit  ; Range Check OK Flag
SET NG_Bit  ; Range Check NG Flag
LD TR0
MOV(021) NodeNo NodeAddr_tmp  ; Inverter No &1 to 31, Inverter No. comparison value
MOV(021) AreaID AreaID_tmp  ; Area Type, Area Type comparison value
MOV(021) AreaNo AreaNo_tmp  ; Area No., Area No. comparison value

; rung 2
LD Ok_Bit  ; Range Check OK Flag
OR END  ; Process end
RSET AddressOk_Bit  ; Address Range Check OK Flag
; rung 3: Index register temporary setting(IR0)
LDNOT AddressOk_Bit  ; Address Range Check OK Flag
MOVR(560) Set_IR IR0  ; Index register temporary setting

; rung 4: Pertinent axis inverter IOM area calculation / #00018000: E0_0 Address / EM is considered as absolute address specification for the common access in CS1/CJ1/CJ1M
LD Ok_Bit  ; Range Check OK Flag
OUT TR0
AND=(300) #B0 AreaID  ; Area Type
MOVR(560) Type_Io IR0  ; I/O area start address
LD TR0
AND=(300) #B1 AreaID  ; Area Type
MOVR(560) Type_W IR0  ; WR area start address
LD TR0
AND=(300) #B2 AreaID  ; Area Type
MOVR(560) Type_H IR0  ; HR area start address
LD TR0
AND=(300) #82 AreaID  ; Area Type
MOVR(560) Type_D IR0  ; DM area start address
LD TR0
AND<=(315) #50 AreaID  ; Area Type
AND>=(325) #6C AreaID  ; Area Type
MOVL(498) #00018000 IR0
-(410) AreaID #50 Tmp_Data[0]  ; Area Type
*U(422) Tmp_Data[0] #8000 Tmp_Data[0]
+L(401) IR0 Tmp_Data[0] IR0
LD TR0
BSET(071) #0 Tmp_Data[0] Tmp_Data[1]
MOV(021) AreaNo Tmp_Data[0]  ; Area No.
MOVL(498) Tmp_Data[0] Offset  ; For Address Calculation
+L(401) IR0 Offset IR0  ; For Address Calculation
-(410) NodeNo &1 Tmp_Data[0]  ; Inverter No &1 to 31
*(420) Tmp_Data[0] &2 Offset  ; For Address Calculation
+L(401) IR0 Offset IR0  ; For Address Calculation

; rung 5: Calculate IR0 addresses only first time
LD Ok_Bit  ; Range Check OK Flag
MOVL(498) IR0 Tmp_IR[0]
SET AddressOk_Bit  ; Address Range Check OK Flag
RSET NG_Bit  ; Range Check NG Flag
; rung 6: Extract temporary IR0 for internal variables
LD AddressOk_Bit  ; Address Range Check OK Flag
MOVL(498) Tmp_IR[0] IR0
; rung 7: Inverterstop ON
LD AddressOk_Bit  ; Address Range Check OK Flag
OUT TR0
AND Execute_ON  ; StartupON
RSTB(533) ^IR0 &0
RSTB(533) ^IR0 &1
ANDTSTN(351) ^IR0 &3
OUT INV_Stop  ; stopCompleted
LD TR0
AND Execute_OFF  ; StartupOFF
RSET Error  ; Error
MOV(021) &0 ErrorID  ; Error Code
OUT END  ; Process end

; rung 8: Create output variables
LD Execute_ON  ; StartupON
OUT TR0
LD AddressOk_Bit  ; Address Range Check OK Flag
LDTST(350) ^IR0 &6
ORTST(350) ^IR0 &14
ORTST(350) ^IR0 &15
ANDLD
OR NG_Bit  ; Range Check NG Flag
ANDLD
OUT Error  ; Error
LD TR0
AND AddressOk_Bit  ; Address Range Check OK Flag
AND INV_Stop  ; stopCompleted
ANDNOT Error  ; Error
OUT Done  ; Deceleration StopCompleted
; rung 9: Create ENO signal
LDNOT NG_Bit  ; Range Check NG Flag
OUT ENO
; rung 10: StartupON/OFF
LD EN
OUT TR0
@LD Execute  ; Startup
OR Execute_ON  ; StartupON
ANDLD
ANDNOT Execute_OFF  ; StartupOFF
OUT Execute_ON  ; StartupON
LD TR0
LD Done  ; Deceleration StopCompleted
OR Error  ; Error
ANDLD
ANDNOT Execute  ; Startup
AND Execute_ON  ; StartupON
OUT Execute_OFF  ; StartupOFF
; rung 11: Detect input data change
LD Execute_ON  ; StartupON
AND AddressOk_Bit  ; Address Range Check OK Flag
LD<>(305) NodeNo NodeAddr_tmp  ; Inverter No &1 to 31, Inverter No. comparison value
OR<>(305) AreaID AreaID_tmp  ; Area Type, Area Type comparison value
OR<>(305) AreaNo AreaNo_tmp  ; Area No., Area No. comparison value
ANDLD
OUT Change  ; Setting Change Flag

; rung 12: Return IR0 from temporary save buffer
LD EN
MOVL(498) SaveIR[0] IR0

## Function block INV080_Reset
; <Error Reset>Resets an Inverter error.
VAR_INPUT
  NodeNo : INT := 1;  (* Inverter No &1 to 31 *)
  Execute : BOOL;  (* Startup *)
  AreaID : WORD := 0082;  (* Area Type *)
  AreaNo : INT;  (* Area No. *)
END_VAR
VAR_OUTPUT
  Done : BOOL;  (* Error ResetCompleted *)
  Error : BOOL;  (* Error *)
  ErrorID : WORD;  (* Error Code *)
END_VAR
VAR
  SaveIR : ARRAY[0..0] OF DINT;  (* IR0 *)
  Ok_Bit : BOOL;  (* Range Check OK Flag *)
  NG_Bit : BOOL;  (* Range Check NG Flag *)
  AddressOk_Bit : BOOL;  (* Address Range Check OK Flag *)
  Change : BOOL;  (* Setting Change Flag *)
  Execute_ON : BOOL;  (* StartupON *)
  END : BOOL;  (* Process end *)
  Offset : DINT;  (* For Address Calculation *)
  AreaNo_tmp : INT;  (* Area No. comparison value *)
  NodeAddr_tmp : INT;  (* Inverter No. comparison value *)
  Tmp_IR : ARRAY[0..0] OF DINT;  (* Temporary IR for internal variables *)
  Error_Reset : BOOL;  (* ErrorResetCompleted *)
  Execute_OFF : BOOL;  (* StartupOFF *)
  Tmp_Data : ARRAY[0..1] OF WORD;  (* internalFor Calculation *)
  P_EM_MaxNo AT A338 : INT;  (* EM bank size *)
  EM_NoCheck : INT;  (* EM bank size check area *)
  Ok_IO : BOOL;  (* Selected CIO area range OK *)
  Ok_WR : BOOL;  (* Selected WR area range OK *)
  Ok_HR : BOOL;  (* Selected HR area range OK *)
  Ok_DM : BOOL;  (* Selected DMarea range OK *)
  Ok_EM : BOOL;  (* Selected EM area range OK *)
  Type_Io AT 0 : WORD;  (* I/O area start address *)
  Type_W AT W0 : WORD;  (* WR area start address *)
  Type_H AT H0 : WORD;  (* HR area start address *)
  Type_D AT D0 : WORD;  (* DM area start address *)
  EM_No_Tmp1 : INT;  (* EM area Calculation area 1 *)
  EM_No_Tmp2 : UDINT;  (* EM area Calculation area 2 *)
  AreaID_tmp : WORD;  (* Area Type comparison value *)
  Set_IR AT 0 : WORD;  (* Index register temporary setting *)
END_VAR

; rung 0: Store IR0 in temporary save buffer
LD EN
MOVL(498) IR0 SaveIR[0]


; rung 1: Check input data range
@LD Execute_ON  ; StartupON
OR Change  ; Setting Change Flag
ANDNOT AddressOk_Bit  ; Address Range Check OK Flag
OUT TR0
AND<=(315) &1 NodeNo  ; Inverter No &1 to 31
AND>=(325) &31 NodeNo  ; Inverter No &1 to 31
OUT Ok_Bit  ; Range Check OK Flag
LD TR0
+(400) #50 P_EM_MaxNo EM_NoCheck  ; EM bank size, EM bank size check area
MOV(021) &62 Tmp_Data[0]
AND Ok_Bit  ; Range Check OK Flag
OUT TR1
AND=(300) #B0 AreaID  ; Area Type
-(410) &6144 Tmp_Data[0] Tmp_Data[1]
AND>(320) Tmp_Data[1] AreaNo  ; Area No.
OUT Ok_IO  ; Selected CIO area range OK
LD TR1
AND=(300) #B1 AreaID  ; Area Type
-(410) &512 Tmp_Data[0] Tmp_Data[1]
AND>(320) Tmp_Data[1] AreaNo  ; Area No.
OUT Ok_WR  ; Selected WR area range OK
LD TR1
AND=(300) #B2 AreaID  ; Area Type
-(410) &512 Tmp_Data[0] Tmp_Data[1]
AND>(320) Tmp_Data[1] AreaNo  ; Area No.
OUT Ok_HR  ; Selected HR area range OK
LD TR1
AND=(300) #82 AreaID  ; Area Type
-(410) &32768 Tmp_Data[0] Tmp_Data[1]
AND>(320) Tmp_Data[1] AreaNo  ; Area No.
OUT Ok_DM  ; Selected DMarea range OK
LD TR1
AND<=(315) #50 AreaID  ; Area Type
AND>=(325) EM_NoCheck AreaID  ; EM bank size check area, Area Type
-(410) &32768 Tmp_Data[0] Tmp_Data[1]
AND>(320) Tmp_Data[1] AreaNo  ; Area No.
OUT Ok_EM  ; Selected EM area range OK
LD TR0
LD Ok_IO  ; Selected CIO area range OK
OR Ok_WR  ; Selected WR area range OK
OR Ok_HR  ; Selected HR area range OK
OR Ok_DM  ; Selected DMarea range OK
OR Ok_EM  ; Selected EM area range OK
ANDLD
OUT Ok_Bit  ; Range Check OK Flag
LD TR0
ANDNOT Ok_Bit  ; Range Check OK Flag
SET NG_Bit  ; Range Check NG Flag
LD TR0
MOV(021) NodeNo NodeAddr_tmp  ; Inverter No &1 to 31, Inverter No. comparison value
MOV(021) AreaID AreaID_tmp  ; Area Type, Area Type comparison value
MOV(021) AreaNo AreaNo_tmp  ; Area No., Area No. comparison value

; rung 2
LD Ok_Bit  ; Range Check OK Flag
OR END  ; Process end
RSET AddressOk_Bit  ; Address Range Check OK Flag
; rung 3: Index register temporary setting(IR0)
LDNOT AddressOk_Bit  ; Address Range Check OK Flag
MOVR(560) Set_IR IR0  ; Index register temporary setting

; rung 4: Pertinent axis inverter IOM area calculation / #00018000: E0_0 Address / EM is considered as absolute address specification for the common access in CS1/CJ1/CJ1M
LD Ok_Bit  ; Range Check OK Flag
OUT TR0
AND=(300) #B0 AreaID  ; Area Type
MOVR(560) Type_Io IR0  ; I/O area start address
LD TR0
AND=(300) #B1 AreaID  ; Area Type
MOVR(560) Type_W IR0  ; WR area start address
LD TR0
AND=(300) #B2 AreaID  ; Area Type
MOVR(560) Type_H IR0  ; HR area start address
LD TR0
AND=(300) #82 AreaID  ; Area Type
MOVR(560) Type_D IR0  ; DM area start address
LD TR0
AND<=(315) #50 AreaID  ; Area Type
AND>=(325) #6C AreaID  ; Area Type
MOVL(498) #00018000 IR0
-(410) AreaID #50 Tmp_Data[0]  ; Area Type
*U(422) Tmp_Data[0] #8000 Tmp_Data[0]
+L(401) IR0 Tmp_Data[0] IR0
LD TR0
BSET(071) #0 Tmp_Data[0] Tmp_Data[1]
MOV(021) AreaNo Tmp_Data[0]  ; Area No.
MOVL(498) Tmp_Data[0] Offset  ; For Address Calculation
+L(401) IR0 Offset IR0  ; For Address Calculation
-(410) NodeNo &1 Tmp_Data[0]  ; Inverter No &1 to 31
*(420) Tmp_Data[0] &2 Offset  ; For Address Calculation
+L(401) IR0 Offset IR0  ; For Address Calculation

; rung 5: Calculate IR0 addresses only first time
LD Ok_Bit  ; Range Check OK Flag
MOVL(498) IR0 Tmp_IR[0]
SET AddressOk_Bit  ; Address Range Check OK Flag
RSET NG_Bit  ; Range Check NG Flag
; rung 6: Extract temporary IR0 for internal variables
LD AddressOk_Bit  ; Address Range Check OK Flag
MOVL(498) Tmp_IR[0] IR0
; rung 7: Error Reset ON
LD AddressOk_Bit  ; Address Range Check OK Flag
AND Execute_ON  ; StartupON
OUT TR0
SETB(532) ^IR0 &2
LDTST(350) ^IR0 &6
ORTST(350) ^IR0 &14
ORTST(350) ^IR0 &15
ANDLD
RSTB(533) ^IR0 &0
RSTB(533) ^IR0 &1
LD TR0
ANDTSTN(351) ^IR0 &6
ANDTSTN(351) ^IR0 &14
ANDTSTN(351) ^IR0 &15
OUT Error_Reset  ; ErrorResetCompleted

; rung 8: Create output variables
LD AddressOk_Bit  ; Address Range Check OK Flag
OUT TR0
AND Execute_ON  ; StartupON
AND Error_Reset  ; ErrorResetCompleted
OUT Done  ; Error ResetCompleted
LD TR0
AND Execute_OFF  ; StartupOFF
MOV(021) &0 ErrorID  ; Error Code
RSTB(533) ^IR0 &2
OUT END  ; Process end
; rung 9
LD NG_Bit  ; Range Check NG Flag
AND Execute_ON  ; StartupON
OUT Error  ; Error
; rung 10: Create ENO signal
LDNOT NG_Bit  ; Range Check NG Flag
OUT ENO
; rung 11: StartupON/OFF
LD EN
OUT TR0
@LD Execute  ; Startup
OR Execute_ON  ; StartupON
ANDLD
ANDNOT Execute_OFF  ; StartupOFF
OUT Execute_ON  ; StartupON
LD TR0
LD Done  ; Error ResetCompleted
OR Error  ; Error
ANDLD
ANDNOT Execute  ; Startup
AND Execute_ON  ; StartupON
OUT Execute_OFF  ; StartupOFF

; rung 12: Detect input data change
LD Execute_ON  ; StartupON
AND AddressOk_Bit  ; Address Range Check OK Flag
LD<>(305) NodeNo NodeAddr_tmp  ; Inverter No &1 to 31, Inverter No. comparison value
OR<>(305) AreaID AreaID_tmp  ; Area Type, Area Type comparison value
OR<>(305) AreaNo AreaNo_tmp  ; Area No., Area No. comparison value
ANDLD
OUT Change  ; Setting Change Flag
; rung 13: Return IR0 from temporary save buffer
LD EN
MOVL(498) SaveIR[0] IR0

## Function block INV200_ReadStatus
; <Status Read>Reads the Inverter status.
VAR_INPUT
  NodeNo : INT := 1;  (* Inverter No &1 to 31 *)
  AreaID : WORD := 0082;  (* Area Type *)
  AreaNo : INT;  (* Area No. *)
END_VAR
VAR_OUTPUT
  ErrorStop : BOOL;  (* Alarm Occurring Flag *)
  Stopping : BOOL;  (* Deceleration Stop Running Flag *)
  StandStill : BOOL;  (* Axis Waiting Flag *)
  ContinuousMotion : BOOL;  (* Execution Flag *)
  ConstantVelocity : BOOL;  (* Speed matching Flag *)
END_VAR
VAR
  Type_W AT W0 : WORD;  (* WR area start address *)
  Type_Io AT 0 : WORD;  (* I/O area start address *)
  Type_H AT H0 : WORD;  (* HR area start address *)
  Type_D AT D0 : WORD;  (* DM area start address *)
  Tmp_IR : ARRAY[0..0] OF DINT;  (* Temporary IR for internal variables *)
  Tmp_Data : ARRAY[0..1] OF WORD;  (* internalFor Calculation *)
  SaveIR : ARRAY[0..0] OF DINT;  (* IR0 *)
  P_EM_MaxNo AT A338 : INT;  (* EM bank size *)
  Ok_WR : BOOL;  (* Selected WR area range OK *)
  Ok_IO : BOOL;  (* Selected CIO area range OK *)
  Ok_HR : BOOL;  (* Selected HR area range OK *)
  Ok_EM : BOOL;  (* Selected EM area range OK *)
  Ok_DM : BOOL;  (* Selected DMarea range OK *)
  Ok_Bit : BOOL;  (* Range Check OK Flag *)
  Offset : DINT;  (* For Address Calculation *)
  NodeAddr_tmp : INT;  (* Inverter No. comparison value *)
  NG_Bit : BOOL;  (* Range Check NG Flag *)
  EM_NoCheck : INT;  (* EM bank size check area *)
  EM_No_Tmp2 : UDINT;  (* EM area Calculation area 2 *)
  EM_No_Tmp1 : INT;  (* EM area Calculation area 1 *)
  Change : BOOL;  (* Setting Change Flag *)
  AreaNo_tmp : INT;  (* Area No. comparison value *)
  AreaID_tmp : WORD;  (* Area Type comparison value *)
  AddressOk_Bit : BOOL;  (* Address Range Check OK Flag *)
  Set_IR AT 0 : WORD;  (* Index register temporary setting *)
END_VAR

; rung 0: Store IR0 in temporary save buffer
LD EN
MOVL(498) IR0 SaveIR[0]


; rung 1: Check input data range
LD EN
ANDNOT AddressOk_Bit  ; Address Range Check OK Flag
OR Change  ; Setting Change Flag
OUT TR0
AND<=(315) &1 NodeNo  ; Inverter No &1 to 31
AND>=(325) &31 NodeNo  ; Inverter No &1 to 31
OUT Ok_Bit  ; Range Check OK Flag
LD TR0
+(400) #50 P_EM_MaxNo EM_NoCheck  ; EM bank size, EM bank size check area
MOV(021) &62 Tmp_Data[0]
AND Ok_Bit  ; Range Check OK Flag
OUT TR1
AND=(300) #B0 AreaID  ; Area Type
-(410) &6144 Tmp_Data[0] Tmp_Data[1]
AND>(320) Tmp_Data[1] AreaNo  ; Area No.
OUT Ok_IO  ; Selected CIO area range OK
LD TR1
AND=(300) #B1 AreaID  ; Area Type
-(410) &512 Tmp_Data[0] Tmp_Data[1]
AND>(320) Tmp_Data[1] AreaNo  ; Area No.
OUT Ok_WR  ; Selected WR area range OK
LD TR1
AND=(300) #B2 AreaID  ; Area Type
-(410) &512 Tmp_Data[0] Tmp_Data[1]
AND>(320) Tmp_Data[1] AreaNo  ; Area No.
OUT Ok_HR  ; Selected HR area range OK
LD TR1
AND=(300) #82 AreaID  ; Area Type
-(410) &32768 Tmp_Data[0] Tmp_Data[1]
AND>(320) Tmp_Data[1] AreaNo  ; Area No.
OUT Ok_DM  ; Selected DMarea range OK
LD TR1
AND<=(315) #50 AreaID  ; Area Type
AND>=(325) EM_NoCheck AreaID  ; EM bank size check area, Area Type
-(410) &32768 Tmp_Data[0] Tmp_Data[1]
AND>(320) Tmp_Data[1] AreaNo  ; Area No.
OUT Ok_EM  ; Selected EM area range OK
LD TR0
LD Ok_IO  ; Selected CIO area range OK
OR Ok_WR  ; Selected WR area range OK
OR Ok_HR  ; Selected HR area range OK
OR Ok_DM  ; Selected DMarea range OK
OR Ok_EM  ; Selected EM area range OK
ANDLD
OUT Ok_Bit  ; Range Check OK Flag
LD TR0
ANDNOT Ok_Bit  ; Range Check OK Flag
SET NG_Bit  ; Range Check NG Flag
LD TR0
MOV(021) NodeNo NodeAddr_tmp  ; Inverter No &1 to 31, Inverter No. comparison value
MOV(021) AreaID AreaID_tmp  ; Area Type, Area Type comparison value
MOV(021) AreaNo AreaNo_tmp  ; Area No., Area No. comparison value

; rung 2
LD Ok_Bit  ; Range Check OK Flag
RSET AddressOk_Bit  ; Address Range Check OK Flag
; rung 3: Index register temporary setting(IR0)
LDNOT AddressOk_Bit  ; Address Range Check OK Flag
MOVR(560) Set_IR IR0  ; Index register temporary setting

; rung 4: Pertinent axis inverter IOM area calculation / #00018000: E0_0 Address / EM is considered as absolute address specification for the common access in CS1/CJ1/CJ1M
LD Ok_Bit  ; Range Check OK Flag
OUT TR0
AND=(300) #B0 AreaID  ; Area Type
MOVR(560) Type_Io IR0  ; I/O area start address
LD TR0
AND=(300) #B1 AreaID  ; Area Type
MOVR(560) Type_W IR0  ; WR area start address
LD TR0
AND=(300) #B2 AreaID  ; Area Type
MOVR(560) Type_H IR0  ; HR area start address
LD TR0
AND=(300) #82 AreaID  ; Area Type
MOVR(560) Type_D IR0  ; DM area start address
LD TR0
AND<=(315) #50 AreaID  ; Area Type
AND>=(325) #6C AreaID  ; Area Type
MOVL(498) #00018000 IR0
-(410) AreaID #50 Tmp_Data[0]  ; Area Type
*U(422) Tmp_Data[0] #8000 Tmp_Data[0]
+L(401) IR0 Tmp_Data[0] IR0
LD TR0
BSET(071) #0 Tmp_Data[0] Tmp_Data[1]
MOV(021) AreaNo Tmp_Data[0]  ; Area No.
MOVL(498) Tmp_Data[0] Offset  ; For Address Calculation
+L(401) IR0 Offset IR0  ; For Address Calculation
-(410) NodeNo &1 Tmp_Data[0]  ; Inverter No &1 to 31
*(420) Tmp_Data[0] &2 Offset  ; For Address Calculation
+L(401) IR0 Offset IR0  ; For Address Calculation

; rung 5: Calculate IR0 addresses only first time
LD Ok_Bit  ; Range Check OK Flag
MOVL(498) IR0 Tmp_IR[0]
SET AddressOk_Bit  ; Address Range Check OK Flag
RSET NG_Bit  ; Range Check NG Flag
; rung 6: Extract temporary IR0 for internal variables
LD AddressOk_Bit  ; Address Range Check OK Flag
MOVL(498) Tmp_IR[0] IR0
; rung 7: Create output variables
LD AddressOk_Bit  ; Address Range Check OK Flag
OUT TR0
LDTST(350) ^IR0 &14
ORTST(350) ^IR0 &15
ANDLD
OUT ErrorStop  ; Alarm Occurring Flag
LD TR0
ANDTSTN(351) ^IR0 &0
ANDTSTN(351) ^IR0 &1
ANDTST(350) ^IR0 &3
OUT Stopping  ; Deceleration Stop Running Flag
LD TR0
ANDTSTN(351) ^IR0 &0
ANDTSTN(351) ^IR0 &1
ANDNOT ErrorStop  ; Alarm Occurring Flag
ANDNOT Stopping  ; Deceleration Stop Running Flag
OUT StandStill  ; Axis Waiting Flag
LD TR0
LDTST(350) ^IR0 &0
ORTST(350) ^IR0 &1
ANDLD
ANDTST(350) ^IR0 &3
OUT ContinuousMotion  ; Execution Flag
LD TR0
ANDTST(350) ^IR0 &5
OUT ConstantVelocity  ; Speed matching Flag
; rung 8: Create ENO signal
LDNOT NG_Bit  ; Range Check NG Flag
OUT ENO

; rung 9: Detect input data change
LD EN
AND AddressOk_Bit  ; Address Range Check OK Flag
LD<>(305) NodeNo NodeAddr_tmp  ; Inverter No &1 to 31, Inverter No. comparison value
OR<>(305) AreaID AreaID_tmp  ; Area Type, Area Type comparison value
OR<>(305) AreaNo AreaNo_tmp  ; Area No., Area No. comparison value
ANDLD
OUT Change  ; Setting Change Flag
; rung 10: Return IR0 from temporary save buffer
LD EN
MOVL(498) SaveIR[0] IR0

## Function block INV201_ReadParameter
; <Parameter Read>Reads the setting value of the specified parameter.
VAR_INPUT
  NodeNo : INT := 1;  (* Inverter No &1 to 31 *)
  ParameterNo : WORD;  (* Parameter No. *)
  MSGAreaID : WORD := 0082;  (* Massage Area Type *)
  MSGAreaNo : INT;  (* Massage Area No. *)
END_VAR
VAR_OUTPUT
  BUSY : BOOL;  (* Processing Flag *)
  Done : BOOL;  (* Normal End *)
  Error : BOOL;  (* Error *)
  ErrorID : WORD;  (* Error Code *)
  Value : WORD;  (* Read Value *)
END_VAR
VAR
  Ok_Bit : BOOL;  (* Range Check OK Flag *)
  NG_Bit : BOOL;  (* Range Check NG Flag *)
  AddressOk_Bit : BOOL;  (* Address Range Check OK Flag *)
  Response_Data : ARRAY[0..20] OF WORD;  (* CMND response data *)
  Tmp_Data : ARRAY[0..4] OF WORD;  (* internalFor Calculation *)
  Phase : WORD;  (* Process order *)
  Command_Data : ARRAY[0..3] OF WORD;  (* CMND command data *)
  Response_CodeNG : BOOL;  (* Response End CodeError *)
  Response_NG : BOOL;  (* Response Error *)
  Response_OK : BOOL;  (* UDPopenNormal *)
  SaveIR : ARRAY[0..0] OF DINT;  (* IR0 *)
  Tmp_IR : ARRAY[0..0] OF DINT;  (* Temporary IR for internal variables *)
  ReStart_Run : BOOL;  (* Retry Flag *)
  P_EM_MaxNo AT A338 : INT;  (* EM bank size *)
  EM_NoCheck : INT;  (* EM bank size check area *)
  Ok_IO : BOOL;  (* Selected CIO area range OK *)
  Ok_WR : BOOL;  (* Selected WR area range OK *)
  Ok_HR : BOOL;  (* Selected HR area range OK *)
  Ok_DM : BOOL;  (* Selected DMarea range OK *)
  Ok_EM : BOOL;  (* Selected EM area range OK *)
  Type_Io AT 0 : WORD;  (* I/O area start address *)
  Type_W AT W0 : WORD;  (* WR area start address *)
  Type_H AT H0 : WORD;  (* HR area start address *)
  Type_D AT D0 : WORD;  (* DM area start address *)
  EM_No_Tmp1 : INT;  (* EM area Calculation area 1 *)
  EM_No_Tmp2 : UDINT;  (* EM area Calculation area 2 *)
  Offset : DINT;  (* For Address Calculation *)
  Set_IR AT 0 : WORD;  (* Index register temporary setting *)
END_VAR

; rung 0: Store IR0 in temporary save buffer
LD EN
MOVL(498) IR0 SaveIR[0]

; rung 1: Check input data range
LD EN
ANDNOT BUSY  ; Processing Flag
OUT TR0
AND<=(315) &1 NodeNo  ; Inverter No &1 to 31
AND>=(325) &31 NodeNo  ; Inverter No &1 to 31
OUT Ok_Bit  ; Range Check OK Flag
LD TR0
+(400) #50 P_EM_MaxNo EM_NoCheck  ; EM bank size, EM bank size check area
MOV(021) &45 Tmp_Data[0]
AND Ok_Bit  ; Range Check OK Flag
OUT TR1
AND=(300) #B0 MSGAreaID  ; Massage Area Type
-(410) &6144 Tmp_Data[0] Tmp_Data[1]
AND>(320) Tmp_Data[1] MSGAreaNo  ; Massage Area No.
OUT Ok_IO  ; Selected CIO area range OK
LD TR1
AND=(300) #B1 MSGAreaID  ; Massage Area Type
-(410) &512 Tmp_Data[0] Tmp_Data[1]
AND>(320) Tmp_Data[1] MSGAreaNo  ; Massage Area No.
OUT Ok_WR  ; Selected WR area range OK
LD TR1
AND=(300) #B2 MSGAreaID  ; Massage Area Type
-(410) &512 Tmp_Data[0] Tmp_Data[1]
AND>(320) Tmp_Data[1] MSGAreaNo  ; Massage Area No.
OUT Ok_HR  ; Selected HR area range OK
LD TR1
AND=(300) #82 MSGAreaID  ; Massage Area Type
-(410) &32768 Tmp_Data[0] Tmp_Data[1]
AND>(320) Tmp_Data[1] MSGAreaNo  ; Massage Area No.
OUT Ok_DM  ; Selected DMarea range OK
LD TR1
AND<=(315) #50 MSGAreaID  ; Massage Area Type
AND>=(325) EM_NoCheck MSGAreaID  ; EM bank size check area, Massage Area Type
-(410) &32768 Tmp_Data[0] Tmp_Data[1]
AND>(320) Tmp_Data[1] MSGAreaNo  ; Massage Area No.
OUT Ok_EM  ; Selected EM area range OK
LD TR0
LD Ok_IO  ; Selected CIO area range OK
OR Ok_WR  ; Selected WR area range OK
OR Ok_HR  ; Selected HR area range OK
OR Ok_DM  ; Selected DMarea range OK
OR Ok_EM  ; Selected EM area range OK
ANDLD
OUT Ok_Bit  ; Range Check OK Flag
LD TR0
ANDNOT Ok_Bit  ; Range Check OK Flag
OUT NG_Bit  ; Range Check NG Flag
LD TR0
RSET AddressOk_Bit  ; Address Range Check OK Flag

; rung 2: Index register temporary setting(IR0)
LDNOT AddressOk_Bit  ; Address Range Check OK Flag
MOVR(560) Set_IR IR0  ; Index register temporary setting

; rung 3: Pertinent axis inverter MSG area calculation / #00018000: E0_0 Address / EM is considered as absolute address specification for the common access in CS1/CJ1/CJ1M
LD Ok_Bit  ; Range Check OK Flag
OUT TR0
AND=(300) #B0 MSGAreaID  ; Massage Area Type
MOVR(560) Type_Io IR0  ; I/O area start address
LD TR0
AND=(300) #B1 MSGAreaID  ; Massage Area Type
MOVR(560) Type_W IR0  ; WR area start address
LD TR0
AND=(300) #B2 MSGAreaID  ; Massage Area Type
MOVR(560) Type_H IR0  ; HR area start address
LD TR0
AND=(300) #82 MSGAreaID  ; Massage Area Type
MOVR(560) Type_D IR0  ; DM area start address
LD TR0
AND<=(315) #50 MSGAreaID  ; Massage Area Type
AND>=(325) #6C MSGAreaID  ; Massage Area Type
MOVL(498) #00018000 IR0
-(410) MSGAreaID #50 Tmp_Data[0]  ; Massage Area Type
*U(422) Tmp_Data[0] #8000 Tmp_Data[0]
+L(401) IR0 Tmp_Data[0] IR0
LD TR0
BSET(071) #0 Tmp_Data[0] Tmp_Data[1]
MOV(021) MSGAreaNo Tmp_Data[0]  ; Massage Area No.
MOVL(498) Tmp_Data[0] Offset  ; For Address Calculation
+L(401) IR0 Offset IR0  ; For Address Calculation

; rung 4: Calculate IR0 addresses only first time
LD Ok_Bit  ; Range Check OK Flag
MOVL(498) IR0 Tmp_IR[0]
SET AddressOk_Bit  ; Address Range Check OK Flag
; rung 5: Extract temporary IR0 for internal variables
LD AddressOk_Bit  ; Address Range Check OK Flag
MOVL(498) Tmp_IR[0] IR0
; rung 6: Ready
LD AddressOk_Bit  ; Address Range Check OK Flag
ANDNOT BUSY  ; Processing Flag
RSET Done  ; Normal End
RSET Error  ; Error
MOV(021) &0 Value  ; Read Value
MOV(021) &0 ErrorID  ; Error Code
MOV(021) &0 Phase  ; Process order
; rung 7: Create Busy Signal
LD AddressOk_Bit  ; Address Range Check OK Flag
OR NG_Bit  ; Range Check NG Flag
ANDNOT Done  ; Normal End
LDNOT Error  ; Error
OR ReStart_Run  ; Retry Flag
ANDLD
OUT BUSY  ; Processing Flag

; rung 8: Phase0 Create Message Command Data
LD AddressOk_Bit  ; Address Range Check OK Flag
AND BUSY  ; Processing Flag
LD=(300) &0 +1^IR0
OR ReStart_Run  ; Retry Flag
ANDLD
AND=(300) &0 Phase  ; Process order
MOVD(083) &8 #0210 Command_Data[0]
MOVD(083) &9 #0010 Command_Data[0]
MOVD(083) NodeNo #0210 Command_Data[1]  ; Inverter No &1 to 31
MOVD(083) #03 #0010 Command_Data[1]
MOV(021) ParameterNo Command_Data[2]  ; Parameter No.
MOV(021) #0001 Command_Data[3]
XFER(070) &4 Command_Data[0] +23^IR0
MOV(021) &1 ^IR0
MOV(021) &1 +1^IR0
MOV(021) &1 Phase  ; Process order

; rung 9: Phase1 Check response code & Inverter model
LD AddressOk_Bit  ; Address Range Check OK Flag
AND BUSY  ; Processing Flag
AND=(300) &0 ^IR0
AND=(300) &1 +1^IR0
AND=(300) &1 Phase  ; Process order
OUT TR0
XFER(070) &21 +2^IR0 Response_Data[0]
LD<>(305) #2804 Response_Data[0]
OR<>(305) &0 Response_Data[1]
ANDLD
OUT Response_CodeNG  ; Response End CodeError
MOV(021) Response_Data[1] ErrorID  ; Error Code
LD TR0
ANDNOT Response_CodeNG  ; Response End CodeError
MOV(021) &2 Phase  ; Process order
LD TR0
MOV(021) &0 Tmp_Data[0]
MOVD(083) ErrorID #0003 Tmp_Data[0]  ; Error Code
AND<>(305) &0 ErrorID  ; Error Code
AND=(300) &1 Tmp_Data[0]
OUT ReStart_Run  ; Retry Flag
MOV(021) &0 Phase  ; Process order
LD TR0
ANDNOT ReStart_Run  ; Retry Flag
MOV(021) &0 +1^IR0

; rung 10: Phase2 Response Data Create data in Read Value Area
LD AddressOk_Bit  ; Address Range Check OK Flag
AND BUSY  ; Processing Flag
AND=(300) &2 Phase  ; Process order
OUT TR0
ANDW(034) Response_Data[2] #00FF Tmp_Data[0]
MOVD(083) Response_Data[2] #0012 Tmp_Data[1]
ANDW(034) Tmp_Data[1] #00FF Tmp_Data[1]
LD=(300) #0083 Tmp_Data[0]
OR<>(305) NodeNo Tmp_Data[1]  ; Inverter No &1 to 31
ANDLD
OUT Response_NG  ; Response Error
MOVD(083) Response_Data[3] #0012 ErrorID  ; Error Code
LD TR0
ANDNOT Response_NG  ; Response Error
MOVD(083) Response_Data[3] #0210 Value  ; Read Value
MOVD(083) Response_Data[4] #0012 Value  ; Read Value
OUT Response_OK  ; UDPopenNormal
; rung 11: Create OK signal
LD BUSY  ; Processing Flag
AND Response_OK  ; UDPopenNormal
OUT Done  ; Normal End
; rung 12: Create NG signal
LD BUSY  ; Processing Flag
LD Response_CodeNG  ; Response End CodeError
OR Response_NG  ; Response Error
OR NG_Bit  ; Range Check NG Flag
ANDLD
OUT Error  ; Error

; rung 13: Create ENO signal
LD AddressOk_Bit  ; Address Range Check OK Flag
OUT ENO
; rung 14: Return IR0 from temporary save buffer
LD EN
MOVL(498) SaveIR[0] IR0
